VERSION 5.8 ;
BUSBITCHARS "[]" ;
DIVIDERCHAR "/" ;
UNITS
    DATABASE MICRONS 1000 ;
END UNITS

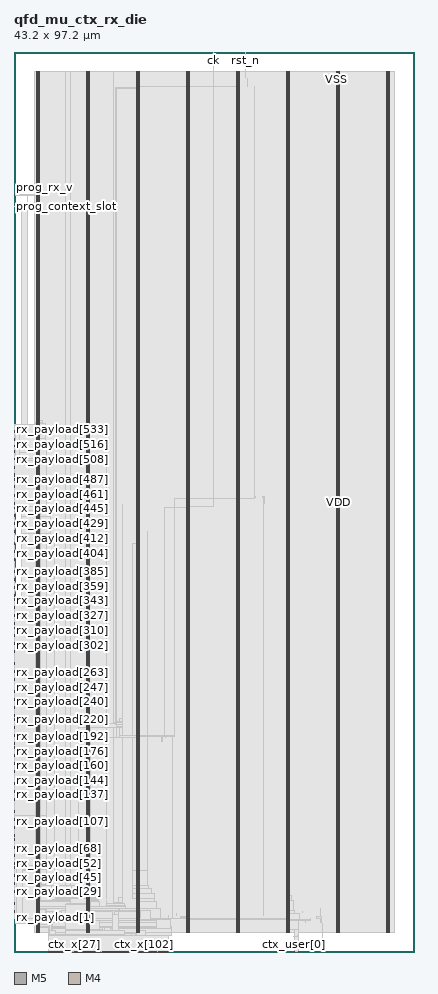
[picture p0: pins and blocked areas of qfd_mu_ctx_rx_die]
MACRO qfd_mu_ctx_rx_die
  FOREIGN qfd_mu_ctx_rx_die 0 0 ;
  CLASS BLOCK ;
  SIZE 43.2 BY 97.2 ;
  PIN ck
    DIRECTION INPUT ;
    USE SIGNAL ;
    PORT
      LAYER M5 ;
        RECT  21.504 97.116 21.528 97.2 ;
    END
  END ck
  PIN ctx_user[0]
    DIRECTION OUTPUT ;
    USE SIGNAL ;
    PORT
      LAYER M5 ;
        RECT  30.24 0 30.264 0.084 ;
    END
  END ctx_user[0]
  PIN ctx_user[1]
    DIRECTION OUTPUT ;
    USE SIGNAL ;
    PORT
      LAYER M5 ;
        RECT  30.72 0 30.744 0.084 ;
    END
  END ctx_user[1]
  PIN ctx_x[0]
    DIRECTION OUTPUT ;
    USE SIGNAL ;
    PORT
      LAYER M5 ;
        RECT  3.744 0 3.768 0.084 ;
    END
  END ctx_x[0]
  PIN ctx_x[100]
    DIRECTION OUTPUT ;
    USE SIGNAL ;
    PORT
      LAYER M5 ;
        RECT  13.824 0 13.848 0.084 ;
    END
  END ctx_x[100]
  PIN ctx_x[101]
    DIRECTION OUTPUT ;
    USE SIGNAL ;
    PORT
      LAYER M5 ;
        RECT  13.92 0 13.944 0.084 ;
    END
  END ctx_x[101]
  PIN ctx_x[102]
    DIRECTION OUTPUT ;
    USE SIGNAL ;
    PORT
      LAYER M5 ;
        RECT  14.016 0 14.04 0.084 ;
    END
  END ctx_x[102]
  PIN ctx_x[103]
    DIRECTION OUTPUT ;
    USE SIGNAL ;
    PORT
      LAYER M5 ;
        RECT  14.112 0 14.136 0.084 ;
    END
  END ctx_x[103]
  PIN ctx_x[104]
    DIRECTION OUTPUT ;
    USE SIGNAL ;
    PORT
      LAYER M5 ;
        RECT  14.208 0 14.232 0.084 ;
    END
  END ctx_x[104]
  PIN ctx_x[105]
    DIRECTION OUTPUT ;
    USE SIGNAL ;
    PORT
      LAYER M5 ;
        RECT  14.304 0 14.328 0.084 ;
    END
  END ctx_x[105]
  PIN ctx_x[106]
    DIRECTION OUTPUT ;
    USE SIGNAL ;
    PORT
      LAYER M5 ;
        RECT  14.4 0 14.424 0.084 ;
    END
  END ctx_x[106]
  PIN ctx_x[107]
    DIRECTION OUTPUT ;
    USE SIGNAL ;
    PORT
      LAYER M5 ;
        RECT  14.544 0 14.568 0.084 ;
    END
  END ctx_x[107]
  PIN ctx_x[108]
    DIRECTION OUTPUT ;
    USE SIGNAL ;
    PORT
      LAYER M5 ;
        RECT  14.64 0 14.664 0.084 ;
    END
  END ctx_x[108]
  PIN ctx_x[109]
    DIRECTION OUTPUT ;
    USE SIGNAL ;
    PORT
      LAYER M5 ;
        RECT  14.736 0 14.76 0.084 ;
    END
  END ctx_x[109]
  PIN ctx_x[10]
    DIRECTION OUTPUT ;
    USE SIGNAL ;
    PORT
      LAYER M5 ;
        RECT  4.752 0 4.776 0.084 ;
    END
  END ctx_x[10]
  PIN ctx_x[110]
    DIRECTION OUTPUT ;
    USE SIGNAL ;
    PORT
      LAYER M5 ;
        RECT  14.832 0 14.856 0.084 ;
    END
  END ctx_x[110]
  PIN ctx_x[111]
    DIRECTION OUTPUT ;
    USE SIGNAL ;
    PORT
      LAYER M5 ;
        RECT  14.928 0 14.952 0.084 ;
    END
  END ctx_x[111]
  PIN ctx_x[112]
    DIRECTION OUTPUT ;
    USE SIGNAL ;
    PORT
      LAYER M5 ;
        RECT  15.024 0 15.048 0.084 ;
    END
  END ctx_x[112]
  PIN ctx_x[113]
    DIRECTION OUTPUT ;
    USE SIGNAL ;
    PORT
      LAYER M5 ;
        RECT  15.12 0 15.144 0.084 ;
    END
  END ctx_x[113]
  PIN ctx_x[114]
    DIRECTION OUTPUT ;
    USE SIGNAL ;
    PORT
      LAYER M5 ;
        RECT  15.216 0 15.24 0.084 ;
    END
  END ctx_x[114]
  PIN ctx_x[115]
    DIRECTION OUTPUT ;
    USE SIGNAL ;
    PORT
      LAYER M5 ;
        RECT  15.312 0 15.336 0.084 ;
    END
  END ctx_x[115]
  PIN ctx_x[116]
    DIRECTION OUTPUT ;
    USE SIGNAL ;
    PORT
      LAYER M5 ;
        RECT  15.408 0 15.432 0.084 ;
    END
  END ctx_x[116]
  PIN ctx_x[117]
    DIRECTION OUTPUT ;
    USE SIGNAL ;
    PORT
      LAYER M5 ;
        RECT  15.552 0 15.576 0.084 ;
    END
  END ctx_x[117]
  PIN ctx_x[118]
    DIRECTION OUTPUT ;
    USE SIGNAL ;
    PORT
      LAYER M5 ;
        RECT  15.648 0 15.672 0.084 ;
    END
  END ctx_x[118]
  PIN ctx_x[119]
    DIRECTION OUTPUT ;
    USE SIGNAL ;
    PORT
      LAYER M5 ;
        RECT  15.744 0 15.768 0.084 ;
    END
  END ctx_x[119]
  PIN ctx_x[11]
    DIRECTION OUTPUT ;
    USE SIGNAL ;
    PORT
      LAYER M5 ;
        RECT  4.848 0 4.872 0.084 ;
    END
  END ctx_x[11]
  PIN ctx_x[120]
    DIRECTION OUTPUT ;
    USE SIGNAL ;
    PORT
      LAYER M5 ;
        RECT  15.84 0 15.864 0.084 ;
    END
  END ctx_x[120]
  PIN ctx_x[121]
    DIRECTION OUTPUT ;
    USE SIGNAL ;
    PORT
      LAYER M5 ;
        RECT  15.936 0 15.96 0.084 ;
    END
  END ctx_x[121]
  PIN ctx_x[122]
    DIRECTION OUTPUT ;
    USE SIGNAL ;
    PORT
      LAYER M5 ;
        RECT  16.032 0 16.056 0.084 ;
    END
  END ctx_x[122]
  PIN ctx_x[123]
    DIRECTION OUTPUT ;
    USE SIGNAL ;
    PORT
      LAYER M5 ;
        RECT  16.128 0 16.152 0.084 ;
    END
  END ctx_x[123]
  PIN ctx_x[124]
    DIRECTION OUTPUT ;
    USE SIGNAL ;
    PORT
      LAYER M5 ;
        RECT  16.224 0 16.248 0.084 ;
    END
  END ctx_x[124]
  PIN ctx_x[125]
    DIRECTION OUTPUT ;
    USE SIGNAL ;
    PORT
      LAYER M5 ;
        RECT  16.32 0 16.344 0.084 ;
    END
  END ctx_x[125]
  PIN ctx_x[126]
    DIRECTION OUTPUT ;
    USE SIGNAL ;
    PORT
      LAYER M5 ;
        RECT  16.416 0 16.44 0.084 ;
    END
  END ctx_x[126]
  PIN ctx_x[127]
    DIRECTION OUTPUT ;
    USE SIGNAL ;
    PORT
      LAYER M5 ;
        RECT  16.56 0 16.584 0.084 ;
    END
  END ctx_x[127]
  PIN ctx_x[128]
    DIRECTION OUTPUT ;
    USE SIGNAL ;
    PORT
      LAYER M5 ;
        RECT  16.656 0 16.68 0.084 ;
    END
  END ctx_x[128]
  PIN ctx_x[12]
    DIRECTION OUTPUT ;
    USE SIGNAL ;
    PORT
      LAYER M5 ;
        RECT  4.944 0 4.968 0.084 ;
    END
  END ctx_x[12]
  PIN ctx_x[13]
    DIRECTION OUTPUT ;
    USE SIGNAL ;
    PORT
      LAYER M5 ;
        RECT  5.04 0 5.064 0.084 ;
    END
  END ctx_x[13]
  PIN ctx_x[14]
    DIRECTION OUTPUT ;
    USE SIGNAL ;
    PORT
      LAYER M5 ;
        RECT  5.136 0 5.16 0.084 ;
    END
  END ctx_x[14]
  PIN ctx_x[15]
    DIRECTION OUTPUT ;
    USE SIGNAL ;
    PORT
      LAYER M5 ;
        RECT  5.232 0 5.256 0.084 ;
    END
  END ctx_x[15]
  PIN ctx_x[16]
    DIRECTION OUTPUT ;
    USE SIGNAL ;
    PORT
      LAYER M5 ;
        RECT  5.328 0 5.352 0.084 ;
    END
  END ctx_x[16]
  PIN ctx_x[17]
    DIRECTION OUTPUT ;
    USE SIGNAL ;
    PORT
      LAYER M5 ;
        RECT  5.472 0 5.496 0.084 ;
    END
  END ctx_x[17]
  PIN ctx_x[18]
    DIRECTION OUTPUT ;
    USE SIGNAL ;
    PORT
      LAYER M5 ;
        RECT  5.568 0 5.592 0.084 ;
    END
  END ctx_x[18]
  PIN ctx_x[19]
    DIRECTION OUTPUT ;
    USE SIGNAL ;
    PORT
      LAYER M5 ;
        RECT  5.664 0 5.688 0.084 ;
    END
  END ctx_x[19]
  PIN ctx_x[1]
    DIRECTION OUTPUT ;
    USE SIGNAL ;
    PORT
      LAYER M5 ;
        RECT  3.84 0 3.864 0.084 ;
    END
  END ctx_x[1]
  PIN ctx_x[20]
    DIRECTION OUTPUT ;
    USE SIGNAL ;
    PORT
      LAYER M5 ;
        RECT  5.76 0 5.784 0.084 ;
    END
  END ctx_x[20]
  PIN ctx_x[21]
    DIRECTION OUTPUT ;
    USE SIGNAL ;
    PORT
      LAYER M5 ;
        RECT  5.856 0 5.88 0.084 ;
    END
  END ctx_x[21]
  PIN ctx_x[22]
    DIRECTION OUTPUT ;
    USE SIGNAL ;
    PORT
      LAYER M5 ;
        RECT  5.952 0 5.976 0.084 ;
    END
  END ctx_x[22]
  PIN ctx_x[23]
    DIRECTION OUTPUT ;
    USE SIGNAL ;
    PORT
      LAYER M5 ;
        RECT  6.048 0 6.072 0.084 ;
    END
  END ctx_x[23]
  PIN ctx_x[24]
    DIRECTION OUTPUT ;
    USE SIGNAL ;
    PORT
      LAYER M5 ;
        RECT  6.144 0 6.168 0.084 ;
    END
  END ctx_x[24]
  PIN ctx_x[25]
    DIRECTION OUTPUT ;
    USE SIGNAL ;
    PORT
      LAYER M5 ;
        RECT  6.24 0 6.264 0.084 ;
    END
  END ctx_x[25]
  PIN ctx_x[26]
    DIRECTION OUTPUT ;
    USE SIGNAL ;
    PORT
      LAYER M5 ;
        RECT  6.336 0 6.36 0.084 ;
    END
  END ctx_x[26]
  PIN ctx_x[27]
    DIRECTION OUTPUT ;
    USE SIGNAL ;
    PORT
      LAYER M5 ;
        RECT  6.48 0 6.504 0.084 ;
    END
  END ctx_x[27]
  PIN ctx_x[28]
    DIRECTION OUTPUT ;
    USE SIGNAL ;
    PORT
      LAYER M5 ;
        RECT  6.576 0 6.6 0.084 ;
    END
  END ctx_x[28]
  PIN ctx_x[29]
    DIRECTION OUTPUT ;
    USE SIGNAL ;
    PORT
      LAYER M5 ;
        RECT  6.672 0 6.696 0.084 ;
    END
  END ctx_x[29]
  PIN ctx_x[2]
    DIRECTION OUTPUT ;
    USE SIGNAL ;
    PORT
      LAYER M5 ;
        RECT  3.936 0 3.96 0.084 ;
    END
  END ctx_x[2]
  PIN ctx_x[30]
    DIRECTION OUTPUT ;
    USE SIGNAL ;
    PORT
      LAYER M5 ;
        RECT  6.768 0 6.792 0.084 ;
    END
  END ctx_x[30]
  PIN ctx_x[31]
    DIRECTION OUTPUT ;
    USE SIGNAL ;
    PORT
      LAYER M5 ;
        RECT  6.864 0 6.888 0.084 ;
    END
  END ctx_x[31]
  PIN ctx_x[32]
    DIRECTION OUTPUT ;
    USE SIGNAL ;
    PORT
      LAYER M5 ;
        RECT  6.96 0 6.984 0.084 ;
    END
  END ctx_x[32]
  PIN ctx_x[33]
    DIRECTION OUTPUT ;
    USE SIGNAL ;
    PORT
      LAYER M5 ;
        RECT  7.056 0 7.08 0.084 ;
    END
  END ctx_x[33]
  PIN ctx_x[34]
    DIRECTION OUTPUT ;
    USE SIGNAL ;
    PORT
      LAYER M5 ;
        RECT  7.152 0 7.176 0.084 ;
    END
  END ctx_x[34]
  PIN ctx_x[35]
    DIRECTION OUTPUT ;
    USE SIGNAL ;
    PORT
      LAYER M5 ;
        RECT  7.248 0 7.272 0.084 ;
    END
  END ctx_x[35]
  PIN ctx_x[36]
    DIRECTION OUTPUT ;
    USE SIGNAL ;
    PORT
      LAYER M5 ;
        RECT  7.344 0 7.368 0.084 ;
    END
  END ctx_x[36]
  PIN ctx_x[37]
    DIRECTION OUTPUT ;
    USE SIGNAL ;
    PORT
      LAYER M5 ;
        RECT  7.488 0 7.512 0.084 ;
    END
  END ctx_x[37]
  PIN ctx_x[38]
    DIRECTION OUTPUT ;
    USE SIGNAL ;
    PORT
      LAYER M5 ;
        RECT  7.584 0 7.608 0.084 ;
    END
  END ctx_x[38]
  PIN ctx_x[39]
    DIRECTION OUTPUT ;
    USE SIGNAL ;
    PORT
      LAYER M5 ;
        RECT  7.68 0 7.704 0.084 ;
    END
  END ctx_x[39]
  PIN ctx_x[3]
    DIRECTION OUTPUT ;
    USE SIGNAL ;
    PORT
      LAYER M5 ;
        RECT  4.032 0 4.056 0.084 ;
    END
  END ctx_x[3]
  PIN ctx_x[40]
    DIRECTION OUTPUT ;
    USE SIGNAL ;
    PORT
      LAYER M5 ;
        RECT  7.776 0 7.8 0.084 ;
    END
  END ctx_x[40]
  PIN ctx_x[41]
    DIRECTION OUTPUT ;
    USE SIGNAL ;
    PORT
      LAYER M5 ;
        RECT  7.872 0 7.896 0.084 ;
    END
  END ctx_x[41]
  PIN ctx_x[42]
    DIRECTION OUTPUT ;
    USE SIGNAL ;
    PORT
      LAYER M5 ;
        RECT  7.968 0 7.992 0.084 ;
    END
  END ctx_x[42]
  PIN ctx_x[43]
    DIRECTION OUTPUT ;
    USE SIGNAL ;
    PORT
      LAYER M5 ;
        RECT  8.064 0 8.088 0.084 ;
    END
  END ctx_x[43]
  PIN ctx_x[44]
    DIRECTION OUTPUT ;
    USE SIGNAL ;
    PORT
      LAYER M5 ;
        RECT  8.16 0 8.184 0.084 ;
    END
  END ctx_x[44]
  PIN ctx_x[45]
    DIRECTION OUTPUT ;
    USE SIGNAL ;
    PORT
      LAYER M5 ;
        RECT  8.256 0 8.28 0.084 ;
    END
  END ctx_x[45]
  PIN ctx_x[46]
    DIRECTION OUTPUT ;
    USE SIGNAL ;
    PORT
      LAYER M5 ;
        RECT  8.352 0 8.376 0.084 ;
    END
  END ctx_x[46]
  PIN ctx_x[47]
    DIRECTION OUTPUT ;
    USE SIGNAL ;
    PORT
      LAYER M5 ;
        RECT  8.496 0 8.52 0.084 ;
    END
  END ctx_x[47]
  PIN ctx_x[48]
    DIRECTION OUTPUT ;
    USE SIGNAL ;
    PORT
      LAYER M5 ;
        RECT  8.592 0 8.616 0.084 ;
    END
  END ctx_x[48]
  PIN ctx_x[49]
    DIRECTION OUTPUT ;
    USE SIGNAL ;
    PORT
      LAYER M5 ;
        RECT  8.688 0 8.712 0.084 ;
    END
  END ctx_x[49]
  PIN ctx_x[4]
    DIRECTION OUTPUT ;
    USE SIGNAL ;
    PORT
      LAYER M5 ;
        RECT  4.128 0 4.152 0.084 ;
    END
  END ctx_x[4]
  PIN ctx_x[50]
    DIRECTION OUTPUT ;
    USE SIGNAL ;
    PORT
      LAYER M5 ;
        RECT  8.784 0 8.808 0.084 ;
    END
  END ctx_x[50]
  PIN ctx_x[51]
    DIRECTION OUTPUT ;
    USE SIGNAL ;
    PORT
      LAYER M5 ;
        RECT  8.88 0 8.904 0.084 ;
    END
  END ctx_x[51]
  PIN ctx_x[52]
    DIRECTION OUTPUT ;
    USE SIGNAL ;
    PORT
      LAYER M5 ;
        RECT  8.976 0 9 0.084 ;
    END
  END ctx_x[52]
  PIN ctx_x[53]
    DIRECTION OUTPUT ;
    USE SIGNAL ;
    PORT
      LAYER M5 ;
        RECT  9.072 0 9.096 0.084 ;
    END
  END ctx_x[53]
  PIN ctx_x[54]
    DIRECTION OUTPUT ;
    USE SIGNAL ;
    PORT
      LAYER M5 ;
        RECT  9.168 0 9.192 0.084 ;
    END
  END ctx_x[54]
  PIN ctx_x[55]
    DIRECTION OUTPUT ;
    USE SIGNAL ;
    PORT
      LAYER M5 ;
        RECT  9.264 0 9.288 0.084 ;
    END
  END ctx_x[55]
  PIN ctx_x[56]
    DIRECTION OUTPUT ;
    USE SIGNAL ;
    PORT
      LAYER M5 ;
        RECT  9.36 0 9.384 0.084 ;
    END
  END ctx_x[56]
  PIN ctx_x[57]
    DIRECTION OUTPUT ;
    USE SIGNAL ;
    PORT
      LAYER M5 ;
        RECT  9.504 0 9.528 0.084 ;
    END
  END ctx_x[57]
  PIN ctx_x[58]
    DIRECTION OUTPUT ;
    USE SIGNAL ;
    PORT
      LAYER M5 ;
        RECT  9.6 0 9.624 0.084 ;
    END
  END ctx_x[58]
  PIN ctx_x[59]
    DIRECTION OUTPUT ;
    USE SIGNAL ;
    PORT
      LAYER M5 ;
        RECT  9.696 0 9.72 0.084 ;
    END
  END ctx_x[59]
  PIN ctx_x[5]
    DIRECTION OUTPUT ;
    USE SIGNAL ;
    PORT
      LAYER M5 ;
        RECT  4.224 0 4.248 0.084 ;
    END
  END ctx_x[5]
  PIN ctx_x[60]
    DIRECTION OUTPUT ;
    USE SIGNAL ;
    PORT
      LAYER M5 ;
        RECT  9.792 0 9.816 0.084 ;
    END
  END ctx_x[60]
  PIN ctx_x[61]
    DIRECTION OUTPUT ;
    USE SIGNAL ;
    PORT
      LAYER M5 ;
        RECT  9.888 0 9.912 0.084 ;
    END
  END ctx_x[61]
  PIN ctx_x[62]
    DIRECTION OUTPUT ;
    USE SIGNAL ;
    PORT
      LAYER M5 ;
        RECT  9.984 0 10.008 0.084 ;
    END
  END ctx_x[62]
  PIN ctx_x[63]
    DIRECTION OUTPUT ;
    USE SIGNAL ;
    PORT
      LAYER M5 ;
        RECT  10.08 0 10.104 0.084 ;
    END
  END ctx_x[63]
  PIN ctx_x[64]
    DIRECTION OUTPUT ;
    USE SIGNAL ;
    PORT
      LAYER M5 ;
        RECT  10.176 0 10.2 0.084 ;
    END
  END ctx_x[64]
  PIN ctx_x[65]
    DIRECTION OUTPUT ;
    USE SIGNAL ;
    PORT
      LAYER M5 ;
        RECT  10.272 0 10.296 0.084 ;
    END
  END ctx_x[65]
  PIN ctx_x[66]
    DIRECTION OUTPUT ;
    USE SIGNAL ;
    PORT
      LAYER M5 ;
        RECT  10.368 0 10.392 0.084 ;
    END
  END ctx_x[66]
  PIN ctx_x[67]
    DIRECTION OUTPUT ;
    USE SIGNAL ;
    PORT
      LAYER M5 ;
        RECT  10.512 0 10.536 0.084 ;
    END
  END ctx_x[67]
  PIN ctx_x[68]
    DIRECTION OUTPUT ;
    USE SIGNAL ;
    PORT
      LAYER M5 ;
        RECT  10.608 0 10.632 0.084 ;
    END
  END ctx_x[68]
  PIN ctx_x[69]
    DIRECTION OUTPUT ;
    USE SIGNAL ;
    PORT
      LAYER M5 ;
        RECT  10.704 0 10.728 0.084 ;
    END
  END ctx_x[69]
  PIN ctx_x[6]
    DIRECTION OUTPUT ;
    USE SIGNAL ;
    PORT
      LAYER M5 ;
        RECT  4.32 0 4.344 0.084 ;
    END
  END ctx_x[6]
  PIN ctx_x[70]
    DIRECTION OUTPUT ;
    USE SIGNAL ;
    PORT
      LAYER M5 ;
        RECT  10.8 0 10.824 0.084 ;
    END
  END ctx_x[70]
  PIN ctx_x[71]
    DIRECTION OUTPUT ;
    USE SIGNAL ;
    PORT
      LAYER M5 ;
        RECT  10.896 0 10.92 0.084 ;
    END
  END ctx_x[71]
  PIN ctx_x[72]
    DIRECTION OUTPUT ;
    USE SIGNAL ;
    PORT
      LAYER M5 ;
        RECT  10.992 0 11.016 0.084 ;
    END
  END ctx_x[72]
  PIN ctx_x[73]
    DIRECTION OUTPUT ;
    USE SIGNAL ;
    PORT
      LAYER M5 ;
        RECT  11.088 0 11.112 0.084 ;
    END
  END ctx_x[73]
  PIN ctx_x[74]
    DIRECTION OUTPUT ;
    USE SIGNAL ;
    PORT
      LAYER M5 ;
        RECT  11.184 0 11.208 0.084 ;
    END
  END ctx_x[74]
  PIN ctx_x[75]
    DIRECTION OUTPUT ;
    USE SIGNAL ;
    PORT
      LAYER M5 ;
        RECT  11.28 0 11.304 0.084 ;
    END
  END ctx_x[75]
  PIN ctx_x[76]
    DIRECTION OUTPUT ;
    USE SIGNAL ;
    PORT
      LAYER M5 ;
        RECT  11.376 0 11.4 0.084 ;
    END
  END ctx_x[76]
  PIN ctx_x[77]
    DIRECTION OUTPUT ;
    USE SIGNAL ;
    PORT
      LAYER M5 ;
        RECT  11.52 0 11.544 0.084 ;
    END
  END ctx_x[77]
  PIN ctx_x[78]
    DIRECTION OUTPUT ;
    USE SIGNAL ;
    PORT
      LAYER M5 ;
        RECT  11.616 0 11.64 0.084 ;
    END
  END ctx_x[78]
  PIN ctx_x[79]
    DIRECTION OUTPUT ;
    USE SIGNAL ;
    PORT
      LAYER M5 ;
        RECT  11.712 0 11.736 0.084 ;
    END
  END ctx_x[79]
  PIN ctx_x[7]
    DIRECTION OUTPUT ;
    USE SIGNAL ;
    PORT
      LAYER M5 ;
        RECT  4.464 0 4.488 0.084 ;
    END
  END ctx_x[7]
  PIN ctx_x[80]
    DIRECTION OUTPUT ;
    USE SIGNAL ;
    PORT
      LAYER M5 ;
        RECT  11.808 0 11.832 0.084 ;
    END
  END ctx_x[80]
  PIN ctx_x[81]
    DIRECTION OUTPUT ;
    USE SIGNAL ;
    PORT
      LAYER M5 ;
        RECT  11.904 0 11.928 0.084 ;
    END
  END ctx_x[81]
  PIN ctx_x[82]
    DIRECTION OUTPUT ;
    USE SIGNAL ;
    PORT
      LAYER M5 ;
        RECT  12 0 12.024 0.084 ;
    END
  END ctx_x[82]
  PIN ctx_x[83]
    DIRECTION OUTPUT ;
    USE SIGNAL ;
    PORT
      LAYER M5 ;
        RECT  12.096 0 12.12 0.084 ;
    END
  END ctx_x[83]
  PIN ctx_x[84]
    DIRECTION OUTPUT ;
    USE SIGNAL ;
    PORT
      LAYER M5 ;
        RECT  12.192 0 12.216 0.084 ;
    END
  END ctx_x[84]
  PIN ctx_x[85]
    DIRECTION OUTPUT ;
    USE SIGNAL ;
    PORT
      LAYER M5 ;
        RECT  12.288 0 12.312 0.084 ;
    END
  END ctx_x[85]
  PIN ctx_x[86]
    DIRECTION OUTPUT ;
    USE SIGNAL ;
    PORT
      LAYER M5 ;
        RECT  12.384 0 12.408 0.084 ;
    END
  END ctx_x[86]
  PIN ctx_x[87]
    DIRECTION OUTPUT ;
    USE SIGNAL ;
    PORT
      LAYER M5 ;
        RECT  12.528 0 12.552 0.084 ;
    END
  END ctx_x[87]
  PIN ctx_x[88]
    DIRECTION OUTPUT ;
    USE SIGNAL ;
    PORT
      LAYER M5 ;
        RECT  12.624 0 12.648 0.084 ;
    END
  END ctx_x[88]
  PIN ctx_x[89]
    DIRECTION OUTPUT ;
    USE SIGNAL ;
    PORT
      LAYER M5 ;
        RECT  12.72 0 12.744 0.084 ;
    END
  END ctx_x[89]
  PIN ctx_x[8]
    DIRECTION OUTPUT ;
    USE SIGNAL ;
    PORT
      LAYER M5 ;
        RECT  4.56 0 4.584 0.084 ;
    END
  END ctx_x[8]
  PIN ctx_x[90]
    DIRECTION OUTPUT ;
    USE SIGNAL ;
    PORT
      LAYER M5 ;
        RECT  12.816 0 12.84 0.084 ;
    END
  END ctx_x[90]
  PIN ctx_x[91]
    DIRECTION OUTPUT ;
    USE SIGNAL ;
    PORT
      LAYER M5 ;
        RECT  12.912 0 12.936 0.084 ;
    END
  END ctx_x[91]
  PIN ctx_x[92]
    DIRECTION OUTPUT ;
    USE SIGNAL ;
    PORT
      LAYER M5 ;
        RECT  13.008 0 13.032 0.084 ;
    END
  END ctx_x[92]
  PIN ctx_x[93]
    DIRECTION OUTPUT ;
    USE SIGNAL ;
    PORT
      LAYER M5 ;
        RECT  13.104 0 13.128 0.084 ;
    END
  END ctx_x[93]
  PIN ctx_x[94]
    DIRECTION OUTPUT ;
    USE SIGNAL ;
    PORT
      LAYER M5 ;
        RECT  13.2 0 13.224 0.084 ;
    END
  END ctx_x[94]
  PIN ctx_x[95]
    DIRECTION OUTPUT ;
    USE SIGNAL ;
    PORT
      LAYER M5 ;
        RECT  13.296 0 13.32 0.084 ;
    END
  END ctx_x[95]
  PIN ctx_x[96]
    DIRECTION OUTPUT ;
    USE SIGNAL ;
    PORT
      LAYER M5 ;
        RECT  13.392 0 13.416 0.084 ;
    END
  END ctx_x[96]
  PIN ctx_x[97]
    DIRECTION OUTPUT ;
    USE SIGNAL ;
    PORT
      LAYER M5 ;
        RECT  13.536 0 13.56 0.084 ;
    END
  END ctx_x[97]
  PIN ctx_x[98]
    DIRECTION OUTPUT ;
    USE SIGNAL ;
    PORT
      LAYER M5 ;
        RECT  13.632 0 13.656 0.084 ;
    END
  END ctx_x[98]
  PIN ctx_x[99]
    DIRECTION OUTPUT ;
    USE SIGNAL ;
    PORT
      LAYER M5 ;
        RECT  13.728 0 13.752 0.084 ;
    END
  END ctx_x[99]
  PIN ctx_x[9]
    DIRECTION OUTPUT ;
    USE SIGNAL ;
    PORT
      LAYER M5 ;
        RECT  4.656 0 4.68 0.084 ;
    END
  END ctx_x[9]
  PIN mu_fault
    DIRECTION OUTPUT ;
    USE SIGNAL ;
    PORT
      LAYER M5 ;
        RECT  33.312 0 33.336 0.084 ;
    END
  END mu_fault
  PIN prog_context_slot
    DIRECTION INPUT ;
    USE SIGNAL ;
    PORT
      LAYER M4 ;
        RECT  0 80.544 0.084 80.568 ;
    END
  END prog_context_slot
  PIN prog_rx_v
    DIRECTION INPUT ;
    USE SIGNAL ;
    PORT
      LAYER M4 ;
        RECT  0 81.744 0.084 81.768 ;
    END
  END prog_rx_v
  PIN rst_n
    DIRECTION INPUT ;
    USE SIGNAL ;
    PORT
      LAYER M5 ;
        RECT  25.008 97.116 25.032 97.2 ;
    END
  END rst_n
  PIN rx_payload[0]
    DIRECTION INPUT ;
    USE SIGNAL ;
    PORT
      LAYER M4 ;
        RECT  0 3.648 0.084 3.672 ;
    END
  END rx_payload[0]
  PIN rx_payload[100]
    DIRECTION INPUT ;
    USE SIGNAL ;
    PORT
      LAYER M4 ;
        RECT  0 13.392 0.084 13.416 ;
    END
  END rx_payload[100]
  PIN rx_payload[101]
    DIRECTION INPUT ;
    USE SIGNAL ;
    PORT
      LAYER M4 ;
        RECT  0 13.488 0.084 13.512 ;
    END
  END rx_payload[101]
  PIN rx_payload[102]
    DIRECTION INPUT ;
    USE SIGNAL ;
    PORT
      LAYER M4 ;
        RECT  0 13.584 0.084 13.608 ;
    END
  END rx_payload[102]
  PIN rx_payload[103]
    DIRECTION INPUT ;
    USE SIGNAL ;
    PORT
      LAYER M4 ;
        RECT  0 13.68 0.084 13.704 ;
    END
  END rx_payload[103]
  PIN rx_payload[104]
    DIRECTION INPUT ;
    USE SIGNAL ;
    PORT
      LAYER M4 ;
        RECT  0 13.776 0.084 13.8 ;
    END
  END rx_payload[104]
  PIN rx_payload[105]
    DIRECTION INPUT ;
    USE SIGNAL ;
    PORT
      LAYER M4 ;
        RECT  0 13.872 0.084 13.896 ;
    END
  END rx_payload[105]
  PIN rx_payload[106]
    DIRECTION INPUT ;
    USE SIGNAL ;
    PORT
      LAYER M4 ;
        RECT  0 13.968 0.084 13.992 ;
    END
  END rx_payload[106]
  PIN rx_payload[107]
    DIRECTION INPUT ;
    USE SIGNAL ;
    PORT
      LAYER M4 ;
        RECT  0 14.064 0.084 14.088 ;
    END
  END rx_payload[107]
  PIN rx_payload[108]
    DIRECTION INPUT ;
    USE SIGNAL ;
    PORT
      LAYER M4 ;
        RECT  0 14.16 0.084 14.184 ;
    END
  END rx_payload[108]
  PIN rx_payload[109]
    DIRECTION INPUT ;
    USE SIGNAL ;
    PORT
      LAYER M4 ;
        RECT  0 14.256 0.084 14.28 ;
    END
  END rx_payload[109]
  PIN rx_payload[10]
    DIRECTION INPUT ;
    USE SIGNAL ;
    PORT
      LAYER M4 ;
        RECT  0 4.608 0.084 4.632 ;
    END
  END rx_payload[10]
  PIN rx_payload[110]
    DIRECTION INPUT ;
    USE SIGNAL ;
    PORT
      LAYER M4 ;
        RECT  0 14.352 0.084 14.376 ;
    END
  END rx_payload[110]
  PIN rx_payload[111]
    DIRECTION INPUT ;
    USE SIGNAL ;
    PORT
      LAYER M4 ;
        RECT  0 14.448 0.084 14.472 ;
    END
  END rx_payload[111]
  PIN rx_payload[112]
    DIRECTION INPUT ;
    USE SIGNAL ;
    PORT
      LAYER M4 ;
        RECT  0 14.544 0.084 14.568 ;
    END
  END rx_payload[112]
  PIN rx_payload[113]
    DIRECTION INPUT ;
    USE SIGNAL ;
    PORT
      LAYER M4 ;
        RECT  0 14.64 0.084 14.664 ;
    END
  END rx_payload[113]
  PIN rx_payload[114]
    DIRECTION INPUT ;
    USE SIGNAL ;
    PORT
      LAYER M4 ;
        RECT  0 14.736 0.084 14.76 ;
    END
  END rx_payload[114]
  PIN rx_payload[115]
    DIRECTION INPUT ;
    USE SIGNAL ;
    PORT
      LAYER M4 ;
        RECT  0 14.832 0.084 14.856 ;
    END
  END rx_payload[115]
  PIN rx_payload[116]
    DIRECTION INPUT ;
    USE SIGNAL ;
    PORT
      LAYER M4 ;
        RECT  0 14.928 0.084 14.952 ;
    END
  END rx_payload[116]
  PIN rx_payload[117]
    DIRECTION INPUT ;
    USE SIGNAL ;
    PORT
      LAYER M4 ;
        RECT  0 15.024 0.084 15.048 ;
    END
  END rx_payload[117]
  PIN rx_payload[118]
    DIRECTION INPUT ;
    USE SIGNAL ;
    PORT
      LAYER M4 ;
        RECT  0 15.12 0.084 15.144 ;
    END
  END rx_payload[118]
  PIN rx_payload[119]
    DIRECTION INPUT ;
    USE SIGNAL ;
    PORT
      LAYER M4 ;
        RECT  0 15.216 0.084 15.24 ;
    END
  END rx_payload[119]
  PIN rx_payload[11]
    DIRECTION INPUT ;
    USE SIGNAL ;
    PORT
      LAYER M4 ;
        RECT  0 4.704 0.084 4.728 ;
    END
  END rx_payload[11]
  PIN rx_payload[120]
    DIRECTION INPUT ;
    USE SIGNAL ;
    PORT
      LAYER M4 ;
        RECT  0 15.312 0.084 15.336 ;
    END
  END rx_payload[120]
  PIN rx_payload[121]
    DIRECTION INPUT ;
    USE SIGNAL ;
    PORT
      LAYER M4 ;
        RECT  0 15.408 0.084 15.432 ;
    END
  END rx_payload[121]
  PIN rx_payload[122]
    DIRECTION INPUT ;
    USE SIGNAL ;
    PORT
      LAYER M4 ;
        RECT  0 15.504 0.084 15.528 ;
    END
  END rx_payload[122]
  PIN rx_payload[123]
    DIRECTION INPUT ;
    USE SIGNAL ;
    PORT
      LAYER M4 ;
        RECT  0 15.6 0.084 15.624 ;
    END
  END rx_payload[123]
  PIN rx_payload[124]
    DIRECTION INPUT ;
    USE SIGNAL ;
    PORT
      LAYER M4 ;
        RECT  0 15.744 0.084 15.768 ;
    END
  END rx_payload[124]
  PIN rx_payload[125]
    DIRECTION INPUT ;
    USE SIGNAL ;
    PORT
      LAYER M4 ;
        RECT  0 15.84 0.084 15.864 ;
    END
  END rx_payload[125]
  PIN rx_payload[126]
    DIRECTION INPUT ;
    USE SIGNAL ;
    PORT
      LAYER M4 ;
        RECT  0 15.936 0.084 15.96 ;
    END
  END rx_payload[126]
  PIN rx_payload[127]
    DIRECTION INPUT ;
    USE SIGNAL ;
    PORT
      LAYER M4 ;
        RECT  0 16.032 0.084 16.056 ;
    END
  END rx_payload[127]
  PIN rx_payload[128]
    DIRECTION INPUT ;
    USE SIGNAL ;
    PORT
      LAYER M4 ;
        RECT  0 16.128 0.084 16.152 ;
    END
  END rx_payload[128]
  PIN rx_payload[129]
    DIRECTION INPUT ;
    USE SIGNAL ;
    PORT
      LAYER M4 ;
        RECT  0 16.224 0.084 16.248 ;
    END
  END rx_payload[129]
  PIN rx_payload[12]
    DIRECTION INPUT ;
    USE SIGNAL ;
    PORT
      LAYER M4 ;
        RECT  0 4.8 0.084 4.824 ;
    END
  END rx_payload[12]
  PIN rx_payload[130]
    DIRECTION INPUT ;
    USE SIGNAL ;
    PORT
      LAYER M4 ;
        RECT  0 16.32 0.084 16.344 ;
    END
  END rx_payload[130]
  PIN rx_payload[131]
    DIRECTION INPUT ;
    USE SIGNAL ;
    PORT
      LAYER M4 ;
        RECT  0 16.416 0.084 16.44 ;
    END
  END rx_payload[131]
  PIN rx_payload[132]
    DIRECTION INPUT ;
    USE SIGNAL ;
    PORT
      LAYER M4 ;
        RECT  0 16.512 0.084 16.536 ;
    END
  END rx_payload[132]
  PIN rx_payload[133]
    DIRECTION INPUT ;
    USE SIGNAL ;
    PORT
      LAYER M4 ;
        RECT  0 16.608 0.084 16.632 ;
    END
  END rx_payload[133]
  PIN rx_payload[134]
    DIRECTION INPUT ;
    USE SIGNAL ;
    PORT
      LAYER M4 ;
        RECT  0 16.704 0.084 16.728 ;
    END
  END rx_payload[134]
  PIN rx_payload[135]
    DIRECTION INPUT ;
    USE SIGNAL ;
    PORT
      LAYER M4 ;
        RECT  0 16.8 0.084 16.824 ;
    END
  END rx_payload[135]
  PIN rx_payload[136]
    DIRECTION INPUT ;
    USE SIGNAL ;
    PORT
      LAYER M4 ;
        RECT  0 16.896 0.084 16.92 ;
    END
  END rx_payload[136]
  PIN rx_payload[137]
    DIRECTION INPUT ;
    USE SIGNAL ;
    PORT
      LAYER M4 ;
        RECT  0 16.992 0.084 17.016 ;
    END
  END rx_payload[137]
  PIN rx_payload[138]
    DIRECTION INPUT ;
    USE SIGNAL ;
    PORT
      LAYER M4 ;
        RECT  0 17.088 0.084 17.112 ;
    END
  END rx_payload[138]
  PIN rx_payload[139]
    DIRECTION INPUT ;
    USE SIGNAL ;
    PORT
      LAYER M4 ;
        RECT  0 17.184 0.084 17.208 ;
    END
  END rx_payload[139]
  PIN rx_payload[13]
    DIRECTION INPUT ;
    USE SIGNAL ;
    PORT
      LAYER M4 ;
        RECT  0 4.896 0.084 4.92 ;
    END
  END rx_payload[13]
  PIN rx_payload[140]
    DIRECTION INPUT ;
    USE SIGNAL ;
    PORT
      LAYER M4 ;
        RECT  0 17.28 0.084 17.304 ;
    END
  END rx_payload[140]
  PIN rx_payload[141]
    DIRECTION INPUT ;
    USE SIGNAL ;
    PORT
      LAYER M4 ;
        RECT  0 17.376 0.084 17.4 ;
    END
  END rx_payload[141]
  PIN rx_payload[142]
    DIRECTION INPUT ;
    USE SIGNAL ;
    PORT
      LAYER M4 ;
        RECT  0 17.472 0.084 17.496 ;
    END
  END rx_payload[142]
  PIN rx_payload[143]
    DIRECTION INPUT ;
    USE SIGNAL ;
    PORT
      LAYER M4 ;
        RECT  0 17.568 0.084 17.592 ;
    END
  END rx_payload[143]
  PIN rx_payload[144]
    DIRECTION INPUT ;
    USE SIGNAL ;
    PORT
      LAYER M4 ;
        RECT  0 17.664 0.084 17.688 ;
    END
  END rx_payload[144]
  PIN rx_payload[145]
    DIRECTION INPUT ;
    USE SIGNAL ;
    PORT
      LAYER M4 ;
        RECT  0 17.76 0.084 17.784 ;
    END
  END rx_payload[145]
  PIN rx_payload[146]
    DIRECTION INPUT ;
    USE SIGNAL ;
    PORT
      LAYER M4 ;
        RECT  0 17.856 0.084 17.88 ;
    END
  END rx_payload[146]
  PIN rx_payload[147]
    DIRECTION INPUT ;
    USE SIGNAL ;
    PORT
      LAYER M4 ;
        RECT  0 17.952 0.084 17.976 ;
    END
  END rx_payload[147]
  PIN rx_payload[148]
    DIRECTION INPUT ;
    USE SIGNAL ;
    PORT
      LAYER M4 ;
        RECT  0 18.048 0.084 18.072 ;
    END
  END rx_payload[148]
  PIN rx_payload[149]
    DIRECTION INPUT ;
    USE SIGNAL ;
    PORT
      LAYER M4 ;
        RECT  0 18.144 0.084 18.168 ;
    END
  END rx_payload[149]
  PIN rx_payload[14]
    DIRECTION INPUT ;
    USE SIGNAL ;
    PORT
      LAYER M4 ;
        RECT  0 4.992 0.084 5.016 ;
    END
  END rx_payload[14]
  PIN rx_payload[150]
    DIRECTION INPUT ;
    USE SIGNAL ;
    PORT
      LAYER M4 ;
        RECT  0 18.24 0.084 18.264 ;
    END
  END rx_payload[150]
  PIN rx_payload[151]
    DIRECTION INPUT ;
    USE SIGNAL ;
    PORT
      LAYER M4 ;
        RECT  0 18.336 0.084 18.36 ;
    END
  END rx_payload[151]
  PIN rx_payload[152]
    DIRECTION INPUT ;
    USE SIGNAL ;
    PORT
      LAYER M4 ;
        RECT  0 18.432 0.084 18.456 ;
    END
  END rx_payload[152]
  PIN rx_payload[153]
    DIRECTION INPUT ;
    USE SIGNAL ;
    PORT
      LAYER M4 ;
        RECT  0 18.528 0.084 18.552 ;
    END
  END rx_payload[153]
  PIN rx_payload[154]
    DIRECTION INPUT ;
    USE SIGNAL ;
    PORT
      LAYER M4 ;
        RECT  0 18.624 0.084 18.648 ;
    END
  END rx_payload[154]
  PIN rx_payload[155]
    DIRECTION INPUT ;
    USE SIGNAL ;
    PORT
      LAYER M4 ;
        RECT  0 18.72 0.084 18.744 ;
    END
  END rx_payload[155]
  PIN rx_payload[156]
    DIRECTION INPUT ;
    USE SIGNAL ;
    PORT
      LAYER M4 ;
        RECT  0 18.816 0.084 18.84 ;
    END
  END rx_payload[156]
  PIN rx_payload[157]
    DIRECTION INPUT ;
    USE SIGNAL ;
    PORT
      LAYER M4 ;
        RECT  0 18.96 0.084 18.984 ;
    END
  END rx_payload[157]
  PIN rx_payload[158]
    DIRECTION INPUT ;
    USE SIGNAL ;
    PORT
      LAYER M4 ;
        RECT  0 19.056 0.084 19.08 ;
    END
  END rx_payload[158]
  PIN rx_payload[159]
    DIRECTION INPUT ;
    USE SIGNAL ;
    PORT
      LAYER M4 ;
        RECT  0 19.152 0.084 19.176 ;
    END
  END rx_payload[159]
  PIN rx_payload[15]
    DIRECTION INPUT ;
    USE SIGNAL ;
    PORT
      LAYER M4 ;
        RECT  0 5.088 0.084 5.112 ;
    END
  END rx_payload[15]
  PIN rx_payload[160]
    DIRECTION INPUT ;
    USE SIGNAL ;
    PORT
      LAYER M4 ;
        RECT  0 19.248 0.084 19.272 ;
    END
  END rx_payload[160]
  PIN rx_payload[161]
    DIRECTION INPUT ;
    USE SIGNAL ;
    PORT
      LAYER M4 ;
        RECT  0 19.344 0.084 19.368 ;
    END
  END rx_payload[161]
  PIN rx_payload[162]
    DIRECTION INPUT ;
    USE SIGNAL ;
    PORT
      LAYER M4 ;
        RECT  0 19.44 0.084 19.464 ;
    END
  END rx_payload[162]
  PIN rx_payload[163]
    DIRECTION INPUT ;
    USE SIGNAL ;
    PORT
      LAYER M4 ;
        RECT  0 19.536 0.084 19.56 ;
    END
  END rx_payload[163]
  PIN rx_payload[164]
    DIRECTION INPUT ;
    USE SIGNAL ;
    PORT
      LAYER M4 ;
        RECT  0 19.632 0.084 19.656 ;
    END
  END rx_payload[164]
  PIN rx_payload[165]
    DIRECTION INPUT ;
    USE SIGNAL ;
    PORT
      LAYER M4 ;
        RECT  0 19.728 0.084 19.752 ;
    END
  END rx_payload[165]
  PIN rx_payload[166]
    DIRECTION INPUT ;
    USE SIGNAL ;
    PORT
      LAYER M4 ;
        RECT  0 19.824 0.084 19.848 ;
    END
  END rx_payload[166]
  PIN rx_payload[167]
    DIRECTION INPUT ;
    USE SIGNAL ;
    PORT
      LAYER M4 ;
        RECT  0 19.92 0.084 19.944 ;
    END
  END rx_payload[167]
  PIN rx_payload[168]
    DIRECTION INPUT ;
    USE SIGNAL ;
    PORT
      LAYER M4 ;
        RECT  0 20.016 0.084 20.04 ;
    END
  END rx_payload[168]
  PIN rx_payload[169]
    DIRECTION INPUT ;
    USE SIGNAL ;
    PORT
      LAYER M4 ;
        RECT  0 20.112 0.084 20.136 ;
    END
  END rx_payload[169]
  PIN rx_payload[16]
    DIRECTION INPUT ;
    USE SIGNAL ;
    PORT
      LAYER M4 ;
        RECT  0 5.184 0.084 5.208 ;
    END
  END rx_payload[16]
  PIN rx_payload[170]
    DIRECTION INPUT ;
    USE SIGNAL ;
    PORT
      LAYER M4 ;
        RECT  0 20.208 0.084 20.232 ;
    END
  END rx_payload[170]
  PIN rx_payload[171]
    DIRECTION INPUT ;
    USE SIGNAL ;
    PORT
      LAYER M4 ;
        RECT  0 20.304 0.084 20.328 ;
    END
  END rx_payload[171]
  PIN rx_payload[172]
    DIRECTION INPUT ;
    USE SIGNAL ;
    PORT
      LAYER M4 ;
        RECT  0 20.4 0.084 20.424 ;
    END
  END rx_payload[172]
  PIN rx_payload[173]
    DIRECTION INPUT ;
    USE SIGNAL ;
    PORT
      LAYER M4 ;
        RECT  0 20.496 0.084 20.52 ;
    END
  END rx_payload[173]
  PIN rx_payload[174]
    DIRECTION INPUT ;
    USE SIGNAL ;
    PORT
      LAYER M4 ;
        RECT  0 20.592 0.084 20.616 ;
    END
  END rx_payload[174]
  PIN rx_payload[175]
    DIRECTION INPUT ;
    USE SIGNAL ;
    PORT
      LAYER M4 ;
        RECT  0 20.688 0.084 20.712 ;
    END
  END rx_payload[175]
  PIN rx_payload[176]
    DIRECTION INPUT ;
    USE SIGNAL ;
    PORT
      LAYER M4 ;
        RECT  0 20.784 0.084 20.808 ;
    END
  END rx_payload[176]
  PIN rx_payload[177]
    DIRECTION INPUT ;
    USE SIGNAL ;
    PORT
      LAYER M4 ;
        RECT  0 20.88 0.084 20.904 ;
    END
  END rx_payload[177]
  PIN rx_payload[178]
    DIRECTION INPUT ;
    USE SIGNAL ;
    PORT
      LAYER M4 ;
        RECT  0 20.976 0.084 21 ;
    END
  END rx_payload[178]
  PIN rx_payload[179]
    DIRECTION INPUT ;
    USE SIGNAL ;
    PORT
      LAYER M4 ;
        RECT  0 21.072 0.084 21.096 ;
    END
  END rx_payload[179]
  PIN rx_payload[17]
    DIRECTION INPUT ;
    USE SIGNAL ;
    PORT
      LAYER M4 ;
        RECT  0 5.28 0.084 5.304 ;
    END
  END rx_payload[17]
  PIN rx_payload[180]
    DIRECTION INPUT ;
    USE SIGNAL ;
    PORT
      LAYER M4 ;
        RECT  0 21.168 0.084 21.192 ;
    END
  END rx_payload[180]
  PIN rx_payload[181]
    DIRECTION INPUT ;
    USE SIGNAL ;
    PORT
      LAYER M4 ;
        RECT  0 21.264 0.084 21.288 ;
    END
  END rx_payload[181]
  PIN rx_payload[182]
    DIRECTION INPUT ;
    USE SIGNAL ;
    PORT
      LAYER M4 ;
        RECT  0 21.36 0.084 21.384 ;
    END
  END rx_payload[182]
  PIN rx_payload[183]
    DIRECTION INPUT ;
    USE SIGNAL ;
    PORT
      LAYER M4 ;
        RECT  0 21.456 0.084 21.48 ;
    END
  END rx_payload[183]
  PIN rx_payload[184]
    DIRECTION INPUT ;
    USE SIGNAL ;
    PORT
      LAYER M4 ;
        RECT  0 21.552 0.084 21.576 ;
    END
  END rx_payload[184]
  PIN rx_payload[185]
    DIRECTION INPUT ;
    USE SIGNAL ;
    PORT
      LAYER M4 ;
        RECT  0 21.648 0.084 21.672 ;
    END
  END rx_payload[185]
  PIN rx_payload[186]
    DIRECTION INPUT ;
    USE SIGNAL ;
    PORT
      LAYER M4 ;
        RECT  0 21.744 0.084 21.768 ;
    END
  END rx_payload[186]
  PIN rx_payload[187]
    DIRECTION INPUT ;
    USE SIGNAL ;
    PORT
      LAYER M4 ;
        RECT  0 21.84 0.084 21.864 ;
    END
  END rx_payload[187]
  PIN rx_payload[188]
    DIRECTION INPUT ;
    USE SIGNAL ;
    PORT
      LAYER M4 ;
        RECT  0 21.936 0.084 21.96 ;
    END
  END rx_payload[188]
  PIN rx_payload[189]
    DIRECTION INPUT ;
    USE SIGNAL ;
    PORT
      LAYER M4 ;
        RECT  0 22.032 0.084 22.056 ;
    END
  END rx_payload[189]
  PIN rx_payload[18]
    DIRECTION INPUT ;
    USE SIGNAL ;
    PORT
      LAYER M4 ;
        RECT  0 5.376 0.084 5.4 ;
    END
  END rx_payload[18]
  PIN rx_payload[190]
    DIRECTION INPUT ;
    USE SIGNAL ;
    PORT
      LAYER M4 ;
        RECT  0 22.128 0.084 22.152 ;
    END
  END rx_payload[190]
  PIN rx_payload[191]
    DIRECTION INPUT ;
    USE SIGNAL ;
    PORT
      LAYER M4 ;
        RECT  0 22.272 0.084 22.296 ;
    END
  END rx_payload[191]
  PIN rx_payload[192]
    DIRECTION INPUT ;
    USE SIGNAL ;
    PORT
      LAYER M4 ;
        RECT  0 22.368 0.084 22.392 ;
    END
  END rx_payload[192]
  PIN rx_payload[193]
    DIRECTION INPUT ;
    USE SIGNAL ;
    PORT
      LAYER M4 ;
        RECT  0 22.464 0.084 22.488 ;
    END
  END rx_payload[193]
  PIN rx_payload[194]
    DIRECTION INPUT ;
    USE SIGNAL ;
    PORT
      LAYER M4 ;
        RECT  0 22.56 0.084 22.584 ;
    END
  END rx_payload[194]
  PIN rx_payload[195]
    DIRECTION INPUT ;
    USE SIGNAL ;
    PORT
      LAYER M4 ;
        RECT  0 22.656 0.084 22.68 ;
    END
  END rx_payload[195]
  PIN rx_payload[196]
    DIRECTION INPUT ;
    USE SIGNAL ;
    PORT
      LAYER M4 ;
        RECT  0 22.752 0.084 22.776 ;
    END
  END rx_payload[196]
  PIN rx_payload[197]
    DIRECTION INPUT ;
    USE SIGNAL ;
    PORT
      LAYER M4 ;
        RECT  0 22.848 0.084 22.872 ;
    END
  END rx_payload[197]
  PIN rx_payload[198]
    DIRECTION INPUT ;
    USE SIGNAL ;
    PORT
      LAYER M4 ;
        RECT  0 22.944 0.084 22.968 ;
    END
  END rx_payload[198]
  PIN rx_payload[199]
    DIRECTION INPUT ;
    USE SIGNAL ;
    PORT
      LAYER M4 ;
        RECT  0 23.04 0.084 23.064 ;
    END
  END rx_payload[199]
  PIN rx_payload[19]
    DIRECTION INPUT ;
    USE SIGNAL ;
    PORT
      LAYER M4 ;
        RECT  0 5.472 0.084 5.496 ;
    END
  END rx_payload[19]
  PIN rx_payload[1]
    DIRECTION INPUT ;
    USE SIGNAL ;
    PORT
      LAYER M4 ;
        RECT  0 3.744 0.084 3.768 ;
    END
  END rx_payload[1]
  PIN rx_payload[200]
    DIRECTION INPUT ;
    USE SIGNAL ;
    PORT
      LAYER M4 ;
        RECT  0 23.136 0.084 23.16 ;
    END
  END rx_payload[200]
  PIN rx_payload[201]
    DIRECTION INPUT ;
    USE SIGNAL ;
    PORT
      LAYER M4 ;
        RECT  0 23.232 0.084 23.256 ;
    END
  END rx_payload[201]
  PIN rx_payload[202]
    DIRECTION INPUT ;
    USE SIGNAL ;
    PORT
      LAYER M4 ;
        RECT  0 23.328 0.084 23.352 ;
    END
  END rx_payload[202]
  PIN rx_payload[203]
    DIRECTION INPUT ;
    USE SIGNAL ;
    PORT
      LAYER M4 ;
        RECT  0 23.424 0.084 23.448 ;
    END
  END rx_payload[203]
  PIN rx_payload[204]
    DIRECTION INPUT ;
    USE SIGNAL ;
    PORT
      LAYER M4 ;
        RECT  0 23.52 0.084 23.544 ;
    END
  END rx_payload[204]
  PIN rx_payload[205]
    DIRECTION INPUT ;
    USE SIGNAL ;
    PORT
      LAYER M4 ;
        RECT  0 23.616 0.084 23.64 ;
    END
  END rx_payload[205]
  PIN rx_payload[206]
    DIRECTION INPUT ;
    USE SIGNAL ;
    PORT
      LAYER M4 ;
        RECT  0 23.712 0.084 23.736 ;
    END
  END rx_payload[206]
  PIN rx_payload[207]
    DIRECTION INPUT ;
    USE SIGNAL ;
    PORT
      LAYER M4 ;
        RECT  0 23.808 0.084 23.832 ;
    END
  END rx_payload[207]
  PIN rx_payload[208]
    DIRECTION INPUT ;
    USE SIGNAL ;
    PORT
      LAYER M4 ;
        RECT  0 23.904 0.084 23.928 ;
    END
  END rx_payload[208]
  PIN rx_payload[209]
    DIRECTION INPUT ;
    USE SIGNAL ;
    PORT
      LAYER M4 ;
        RECT  0 24 0.084 24.024 ;
    END
  END rx_payload[209]
  PIN rx_payload[20]
    DIRECTION INPUT ;
    USE SIGNAL ;
    PORT
      LAYER M4 ;
        RECT  0 5.568 0.084 5.592 ;
    END
  END rx_payload[20]
  PIN rx_payload[210]
    DIRECTION INPUT ;
    USE SIGNAL ;
    PORT
      LAYER M4 ;
        RECT  0 24.096 0.084 24.12 ;
    END
  END rx_payload[210]
  PIN rx_payload[211]
    DIRECTION INPUT ;
    USE SIGNAL ;
    PORT
      LAYER M4 ;
        RECT  0 24.192 0.084 24.216 ;
    END
  END rx_payload[211]
  PIN rx_payload[212]
    DIRECTION INPUT ;
    USE SIGNAL ;
    PORT
      LAYER M4 ;
        RECT  0 24.288 0.084 24.312 ;
    END
  END rx_payload[212]
  PIN rx_payload[213]
    DIRECTION INPUT ;
    USE SIGNAL ;
    PORT
      LAYER M4 ;
        RECT  0 24.384 0.084 24.408 ;
    END
  END rx_payload[213]
  PIN rx_payload[214]
    DIRECTION INPUT ;
    USE SIGNAL ;
    PORT
      LAYER M4 ;
        RECT  0 24.48 0.084 24.504 ;
    END
  END rx_payload[214]
  PIN rx_payload[215]
    DIRECTION INPUT ;
    USE SIGNAL ;
    PORT
      LAYER M4 ;
        RECT  0 24.576 0.084 24.6 ;
    END
  END rx_payload[215]
  PIN rx_payload[216]
    DIRECTION INPUT ;
    USE SIGNAL ;
    PORT
      LAYER M4 ;
        RECT  0 24.672 0.084 24.696 ;
    END
  END rx_payload[216]
  PIN rx_payload[217]
    DIRECTION INPUT ;
    USE SIGNAL ;
    PORT
      LAYER M4 ;
        RECT  0 24.768 0.084 24.792 ;
    END
  END rx_payload[217]
  PIN rx_payload[218]
    DIRECTION INPUT ;
    USE SIGNAL ;
    PORT
      LAYER M4 ;
        RECT  0 24.864 0.084 24.888 ;
    END
  END rx_payload[218]
  PIN rx_payload[219]
    DIRECTION INPUT ;
    USE SIGNAL ;
    PORT
      LAYER M4 ;
        RECT  0 24.96 0.084 24.984 ;
    END
  END rx_payload[219]
  PIN rx_payload[21]
    DIRECTION INPUT ;
    USE SIGNAL ;
    PORT
      LAYER M4 ;
        RECT  0 5.664 0.084 5.688 ;
    END
  END rx_payload[21]
  PIN rx_payload[220]
    DIRECTION INPUT ;
    USE SIGNAL ;
    PORT
      LAYER M4 ;
        RECT  0 25.056 0.084 25.08 ;
    END
  END rx_payload[220]
  PIN rx_payload[221]
    DIRECTION INPUT ;
    USE SIGNAL ;
    PORT
      LAYER M4 ;
        RECT  0 25.152 0.084 25.176 ;
    END
  END rx_payload[221]
  PIN rx_payload[222]
    DIRECTION INPUT ;
    USE SIGNAL ;
    PORT
      LAYER M4 ;
        RECT  0 25.248 0.084 25.272 ;
    END
  END rx_payload[222]
  PIN rx_payload[223]
    DIRECTION INPUT ;
    USE SIGNAL ;
    PORT
      LAYER M4 ;
        RECT  0 25.344 0.084 25.368 ;
    END
  END rx_payload[223]
  PIN rx_payload[224]
    DIRECTION INPUT ;
    USE SIGNAL ;
    PORT
      LAYER M4 ;
        RECT  0 25.488 0.084 25.512 ;
    END
  END rx_payload[224]
  PIN rx_payload[225]
    DIRECTION INPUT ;
    USE SIGNAL ;
    PORT
      LAYER M4 ;
        RECT  0 25.584 0.084 25.608 ;
    END
  END rx_payload[225]
  PIN rx_payload[226]
    DIRECTION INPUT ;
    USE SIGNAL ;
    PORT
      LAYER M4 ;
        RECT  0 25.68 0.084 25.704 ;
    END
  END rx_payload[226]
  PIN rx_payload[227]
    DIRECTION INPUT ;
    USE SIGNAL ;
    PORT
      LAYER M4 ;
        RECT  0 25.776 0.084 25.8 ;
    END
  END rx_payload[227]
  PIN rx_payload[228]
    DIRECTION INPUT ;
    USE SIGNAL ;
    PORT
      LAYER M4 ;
        RECT  0 25.872 0.084 25.896 ;
    END
  END rx_payload[228]
  PIN rx_payload[229]
    DIRECTION INPUT ;
    USE SIGNAL ;
    PORT
      LAYER M4 ;
        RECT  0 25.968 0.084 25.992 ;
    END
  END rx_payload[229]
  PIN rx_payload[22]
    DIRECTION INPUT ;
    USE SIGNAL ;
    PORT
      LAYER M4 ;
        RECT  0 5.76 0.084 5.784 ;
    END
  END rx_payload[22]
  PIN rx_payload[230]
    DIRECTION INPUT ;
    USE SIGNAL ;
    PORT
      LAYER M4 ;
        RECT  0 26.064 0.084 26.088 ;
    END
  END rx_payload[230]
  PIN rx_payload[231]
    DIRECTION INPUT ;
    USE SIGNAL ;
    PORT
      LAYER M4 ;
        RECT  0 26.16 0.084 26.184 ;
    END
  END rx_payload[231]
  PIN rx_payload[232]
    DIRECTION INPUT ;
    USE SIGNAL ;
    PORT
      LAYER M4 ;
        RECT  0 26.256 0.084 26.28 ;
    END
  END rx_payload[232]
  PIN rx_payload[233]
    DIRECTION INPUT ;
    USE SIGNAL ;
    PORT
      LAYER M4 ;
        RECT  0 26.352 0.084 26.376 ;
    END
  END rx_payload[233]
  PIN rx_payload[234]
    DIRECTION INPUT ;
    USE SIGNAL ;
    PORT
      LAYER M4 ;
        RECT  0 26.448 0.084 26.472 ;
    END
  END rx_payload[234]
  PIN rx_payload[235]
    DIRECTION INPUT ;
    USE SIGNAL ;
    PORT
      LAYER M4 ;
        RECT  0 26.544 0.084 26.568 ;
    END
  END rx_payload[235]
  PIN rx_payload[236]
    DIRECTION INPUT ;
    USE SIGNAL ;
    PORT
      LAYER M4 ;
        RECT  0 26.64 0.084 26.664 ;
    END
  END rx_payload[236]
  PIN rx_payload[237]
    DIRECTION INPUT ;
    USE SIGNAL ;
    PORT
      LAYER M4 ;
        RECT  0 26.736 0.084 26.76 ;
    END
  END rx_payload[237]
  PIN rx_payload[238]
    DIRECTION INPUT ;
    USE SIGNAL ;
    PORT
      LAYER M4 ;
        RECT  0 26.832 0.084 26.856 ;
    END
  END rx_payload[238]
  PIN rx_payload[239]
    DIRECTION INPUT ;
    USE SIGNAL ;
    PORT
      LAYER M4 ;
        RECT  0 26.928 0.084 26.952 ;
    END
  END rx_payload[239]
  PIN rx_payload[23]
    DIRECTION INPUT ;
    USE SIGNAL ;
    PORT
      LAYER M4 ;
        RECT  0 5.856 0.084 5.88 ;
    END
  END rx_payload[23]
  PIN rx_payload[240]
    DIRECTION INPUT ;
    USE SIGNAL ;
    PORT
      LAYER M4 ;
        RECT  0 27.024 0.084 27.048 ;
    END
  END rx_payload[240]
  PIN rx_payload[241]
    DIRECTION INPUT ;
    USE SIGNAL ;
    PORT
      LAYER M4 ;
        RECT  0 27.12 0.084 27.144 ;
    END
  END rx_payload[241]
  PIN rx_payload[242]
    DIRECTION INPUT ;
    USE SIGNAL ;
    PORT
      LAYER M4 ;
        RECT  0 27.216 0.084 27.24 ;
    END
  END rx_payload[242]
  PIN rx_payload[243]
    DIRECTION INPUT ;
    USE SIGNAL ;
    PORT
      LAYER M4 ;
        RECT  0 27.312 0.084 27.336 ;
    END
  END rx_payload[243]
  PIN rx_payload[244]
    DIRECTION INPUT ;
    USE SIGNAL ;
    PORT
      LAYER M4 ;
        RECT  0 27.408 0.084 27.432 ;
    END
  END rx_payload[244]
  PIN rx_payload[245]
    DIRECTION INPUT ;
    USE SIGNAL ;
    PORT
      LAYER M4 ;
        RECT  0 27.504 0.084 27.528 ;
    END
  END rx_payload[245]
  PIN rx_payload[246]
    DIRECTION INPUT ;
    USE SIGNAL ;
    PORT
      LAYER M4 ;
        RECT  0 27.6 0.084 27.624 ;
    END
  END rx_payload[246]
  PIN rx_payload[247]
    DIRECTION INPUT ;
    USE SIGNAL ;
    PORT
      LAYER M4 ;
        RECT  0 27.696 0.084 27.72 ;
    END
  END rx_payload[247]
  PIN rx_payload[248]
    DIRECTION INPUT ;
    USE SIGNAL ;
    PORT
      LAYER M4 ;
        RECT  0 27.792 0.084 27.816 ;
    END
  END rx_payload[248]
  PIN rx_payload[249]
    DIRECTION INPUT ;
    USE SIGNAL ;
    PORT
      LAYER M4 ;
        RECT  0 27.888 0.084 27.912 ;
    END
  END rx_payload[249]
  PIN rx_payload[24]
    DIRECTION INPUT ;
    USE SIGNAL ;
    PORT
      LAYER M4 ;
        RECT  0 5.952 0.084 5.976 ;
    END
  END rx_payload[24]
  PIN rx_payload[250]
    DIRECTION INPUT ;
    USE SIGNAL ;
    PORT
      LAYER M4 ;
        RECT  0 27.984 0.084 28.008 ;
    END
  END rx_payload[250]
  PIN rx_payload[251]
    DIRECTION INPUT ;
    USE SIGNAL ;
    PORT
      LAYER M4 ;
        RECT  0 28.08 0.084 28.104 ;
    END
  END rx_payload[251]
  PIN rx_payload[252]
    DIRECTION INPUT ;
    USE SIGNAL ;
    PORT
      LAYER M4 ;
        RECT  0 28.176 0.084 28.2 ;
    END
  END rx_payload[252]
  PIN rx_payload[253]
    DIRECTION INPUT ;
    USE SIGNAL ;
    PORT
      LAYER M4 ;
        RECT  0 28.272 0.084 28.296 ;
    END
  END rx_payload[253]
  PIN rx_payload[254]
    DIRECTION INPUT ;
    USE SIGNAL ;
    PORT
      LAYER M4 ;
        RECT  0 28.368 0.084 28.392 ;
    END
  END rx_payload[254]
  PIN rx_payload[255]
    DIRECTION INPUT ;
    USE SIGNAL ;
    PORT
      LAYER M4 ;
        RECT  0 28.464 0.084 28.488 ;
    END
  END rx_payload[255]
  PIN rx_payload[256]
    DIRECTION INPUT ;
    USE SIGNAL ;
    PORT
      LAYER M4 ;
        RECT  0 28.56 0.084 28.584 ;
    END
  END rx_payload[256]
  PIN rx_payload[257]
    DIRECTION INPUT ;
    USE SIGNAL ;
    PORT
      LAYER M4 ;
        RECT  0 28.704 0.084 28.728 ;
    END
  END rx_payload[257]
  PIN rx_payload[258]
    DIRECTION INPUT ;
    USE SIGNAL ;
    PORT
      LAYER M4 ;
        RECT  0 28.8 0.084 28.824 ;
    END
  END rx_payload[258]
  PIN rx_payload[259]
    DIRECTION INPUT ;
    USE SIGNAL ;
    PORT
      LAYER M4 ;
        RECT  0 28.896 0.084 28.92 ;
    END
  END rx_payload[259]
  PIN rx_payload[25]
    DIRECTION INPUT ;
    USE SIGNAL ;
    PORT
      LAYER M4 ;
        RECT  0 6.096 0.084 6.12 ;
    END
  END rx_payload[25]
  PIN rx_payload[260]
    DIRECTION INPUT ;
    USE SIGNAL ;
    PORT
      LAYER M4 ;
        RECT  0 28.992 0.084 29.016 ;
    END
  END rx_payload[260]
  PIN rx_payload[261]
    DIRECTION INPUT ;
    USE SIGNAL ;
    PORT
      LAYER M4 ;
        RECT  0 29.088 0.084 29.112 ;
    END
  END rx_payload[261]
  PIN rx_payload[262]
    DIRECTION INPUT ;
    USE SIGNAL ;
    PORT
      LAYER M4 ;
        RECT  0 29.184 0.084 29.208 ;
    END
  END rx_payload[262]
  PIN rx_payload[263]
    DIRECTION INPUT ;
    USE SIGNAL ;
    PORT
      LAYER M4 ;
        RECT  0 29.28 0.084 29.304 ;
    END
  END rx_payload[263]
  PIN rx_payload[264]
    DIRECTION INPUT ;
    USE SIGNAL ;
    PORT
      LAYER M4 ;
        RECT  0 29.376 0.084 29.4 ;
    END
  END rx_payload[264]
  PIN rx_payload[265]
    DIRECTION INPUT ;
    USE SIGNAL ;
    PORT
      LAYER M4 ;
        RECT  0 29.472 0.084 29.496 ;
    END
  END rx_payload[265]
  PIN rx_payload[266]
    DIRECTION INPUT ;
    USE SIGNAL ;
    PORT
      LAYER M4 ;
        RECT  0 29.568 0.084 29.592 ;
    END
  END rx_payload[266]
  PIN rx_payload[267]
    DIRECTION INPUT ;
    USE SIGNAL ;
    PORT
      LAYER M4 ;
        RECT  0 29.664 0.084 29.688 ;
    END
  END rx_payload[267]
  PIN rx_payload[268]
    DIRECTION INPUT ;
    USE SIGNAL ;
    PORT
      LAYER M4 ;
        RECT  0 29.76 0.084 29.784 ;
    END
  END rx_payload[268]
  PIN rx_payload[269]
    DIRECTION INPUT ;
    USE SIGNAL ;
    PORT
      LAYER M4 ;
        RECT  0 29.856 0.084 29.88 ;
    END
  END rx_payload[269]
  PIN rx_payload[26]
    DIRECTION INPUT ;
    USE SIGNAL ;
    PORT
      LAYER M4 ;
        RECT  0 6.192 0.084 6.216 ;
    END
  END rx_payload[26]
  PIN rx_payload[270]
    DIRECTION INPUT ;
    USE SIGNAL ;
    PORT
      LAYER M4 ;
        RECT  0 29.952 0.084 29.976 ;
    END
  END rx_payload[270]
  PIN rx_payload[271]
    DIRECTION INPUT ;
    USE SIGNAL ;
    PORT
      LAYER M4 ;
        RECT  0 30.048 0.084 30.072 ;
    END
  END rx_payload[271]
  PIN rx_payload[272]
    DIRECTION INPUT ;
    USE SIGNAL ;
    PORT
      LAYER M4 ;
        RECT  0 30.144 0.084 30.168 ;
    END
  END rx_payload[272]
  PIN rx_payload[273]
    DIRECTION INPUT ;
    USE SIGNAL ;
    PORT
      LAYER M4 ;
        RECT  0 30.24 0.084 30.264 ;
    END
  END rx_payload[273]
  PIN rx_payload[274]
    DIRECTION INPUT ;
    USE SIGNAL ;
    PORT
      LAYER M4 ;
        RECT  0 30.336 0.084 30.36 ;
    END
  END rx_payload[274]
  PIN rx_payload[275]
    DIRECTION INPUT ;
    USE SIGNAL ;
    PORT
      LAYER M4 ;
        RECT  0 30.432 0.084 30.456 ;
    END
  END rx_payload[275]
  PIN rx_payload[276]
    DIRECTION INPUT ;
    USE SIGNAL ;
    PORT
      LAYER M4 ;
        RECT  0 30.528 0.084 30.552 ;
    END
  END rx_payload[276]
  PIN rx_payload[277]
    DIRECTION INPUT ;
    USE SIGNAL ;
    PORT
      LAYER M4 ;
        RECT  0 30.624 0.084 30.648 ;
    END
  END rx_payload[277]
  PIN rx_payload[278]
    DIRECTION INPUT ;
    USE SIGNAL ;
    PORT
      LAYER M4 ;
        RECT  0 30.72 0.084 30.744 ;
    END
  END rx_payload[278]
  PIN rx_payload[279]
    DIRECTION INPUT ;
    USE SIGNAL ;
    PORT
      LAYER M4 ;
        RECT  0 30.816 0.084 30.84 ;
    END
  END rx_payload[279]
  PIN rx_payload[27]
    DIRECTION INPUT ;
    USE SIGNAL ;
    PORT
      LAYER M4 ;
        RECT  0 6.288 0.084 6.312 ;
    END
  END rx_payload[27]
  PIN rx_payload[280]
    DIRECTION INPUT ;
    USE SIGNAL ;
    PORT
      LAYER M4 ;
        RECT  0 30.912 0.084 30.936 ;
    END
  END rx_payload[280]
  PIN rx_payload[281]
    DIRECTION INPUT ;
    USE SIGNAL ;
    PORT
      LAYER M4 ;
        RECT  0 31.008 0.084 31.032 ;
    END
  END rx_payload[281]
  PIN rx_payload[282]
    DIRECTION INPUT ;
    USE SIGNAL ;
    PORT
      LAYER M4 ;
        RECT  0 31.104 0.084 31.128 ;
    END
  END rx_payload[282]
  PIN rx_payload[283]
    DIRECTION INPUT ;
    USE SIGNAL ;
    PORT
      LAYER M4 ;
        RECT  0 31.2 0.084 31.224 ;
    END
  END rx_payload[283]
  PIN rx_payload[284]
    DIRECTION INPUT ;
    USE SIGNAL ;
    PORT
      LAYER M4 ;
        RECT  0 31.296 0.084 31.32 ;
    END
  END rx_payload[284]
  PIN rx_payload[285]
    DIRECTION INPUT ;
    USE SIGNAL ;
    PORT
      LAYER M4 ;
        RECT  0 31.392 0.084 31.416 ;
    END
  END rx_payload[285]
  PIN rx_payload[286]
    DIRECTION INPUT ;
    USE SIGNAL ;
    PORT
      LAYER M4 ;
        RECT  0 31.488 0.084 31.512 ;
    END
  END rx_payload[286]
  PIN rx_payload[287]
    DIRECTION INPUT ;
    USE SIGNAL ;
    PORT
      LAYER M4 ;
        RECT  0 31.584 0.084 31.608 ;
    END
  END rx_payload[287]
  PIN rx_payload[288]
    DIRECTION INPUT ;
    USE SIGNAL ;
    PORT
      LAYER M4 ;
        RECT  0 31.68 0.084 31.704 ;
    END
  END rx_payload[288]
  PIN rx_payload[289]
    DIRECTION INPUT ;
    USE SIGNAL ;
    PORT
      LAYER M4 ;
        RECT  0 31.776 0.084 31.8 ;
    END
  END rx_payload[289]
  PIN rx_payload[28]
    DIRECTION INPUT ;
    USE SIGNAL ;
    PORT
      LAYER M4 ;
        RECT  0 6.384 0.084 6.408 ;
    END
  END rx_payload[28]
  PIN rx_payload[290]
    DIRECTION INPUT ;
    USE SIGNAL ;
    PORT
      LAYER M4 ;
        RECT  0 31.92 0.084 31.944 ;
    END
  END rx_payload[290]
  PIN rx_payload[291]
    DIRECTION INPUT ;
    USE SIGNAL ;
    PORT
      LAYER M4 ;
        RECT  0 32.016 0.084 32.04 ;
    END
  END rx_payload[291]
  PIN rx_payload[292]
    DIRECTION INPUT ;
    USE SIGNAL ;
    PORT
      LAYER M4 ;
        RECT  0 32.112 0.084 32.136 ;
    END
  END rx_payload[292]
  PIN rx_payload[293]
    DIRECTION INPUT ;
    USE SIGNAL ;
    PORT
      LAYER M4 ;
        RECT  0 32.208 0.084 32.232 ;
    END
  END rx_payload[293]
  PIN rx_payload[294]
    DIRECTION INPUT ;
    USE SIGNAL ;
    PORT
      LAYER M4 ;
        RECT  0 32.304 0.084 32.328 ;
    END
  END rx_payload[294]
  PIN rx_payload[295]
    DIRECTION INPUT ;
    USE SIGNAL ;
    PORT
      LAYER M4 ;
        RECT  0 32.4 0.084 32.424 ;
    END
  END rx_payload[295]
  PIN rx_payload[296]
    DIRECTION INPUT ;
    USE SIGNAL ;
    PORT
      LAYER M4 ;
        RECT  0 32.496 0.084 32.52 ;
    END
  END rx_payload[296]
  PIN rx_payload[297]
    DIRECTION INPUT ;
    USE SIGNAL ;
    PORT
      LAYER M4 ;
        RECT  0 32.592 0.084 32.616 ;
    END
  END rx_payload[297]
  PIN rx_payload[298]
    DIRECTION INPUT ;
    USE SIGNAL ;
    PORT
      LAYER M4 ;
        RECT  0 32.688 0.084 32.712 ;
    END
  END rx_payload[298]
  PIN rx_payload[299]
    DIRECTION INPUT ;
    USE SIGNAL ;
    PORT
      LAYER M4 ;
        RECT  0 32.784 0.084 32.808 ;
    END
  END rx_payload[299]
  PIN rx_payload[29]
    DIRECTION INPUT ;
    USE SIGNAL ;
    PORT
      LAYER M4 ;
        RECT  0 6.48 0.084 6.504 ;
    END
  END rx_payload[29]
  PIN rx_payload[2]
    DIRECTION INPUT ;
    USE SIGNAL ;
    PORT
      LAYER M4 ;
        RECT  0 3.84 0.084 3.864 ;
    END
  END rx_payload[2]
  PIN rx_payload[300]
    DIRECTION INPUT ;
    USE SIGNAL ;
    PORT
      LAYER M4 ;
        RECT  0 32.88 0.084 32.904 ;
    END
  END rx_payload[300]
  PIN rx_payload[301]
    DIRECTION INPUT ;
    USE SIGNAL ;
    PORT
      LAYER M4 ;
        RECT  0 32.976 0.084 33 ;
    END
  END rx_payload[301]
  PIN rx_payload[302]
    DIRECTION INPUT ;
    USE SIGNAL ;
    PORT
      LAYER M4 ;
        RECT  0 33.072 0.084 33.096 ;
    END
  END rx_payload[302]
  PIN rx_payload[303]
    DIRECTION INPUT ;
    USE SIGNAL ;
    PORT
      LAYER M4 ;
        RECT  0 33.168 0.084 33.192 ;
    END
  END rx_payload[303]
  PIN rx_payload[304]
    DIRECTION INPUT ;
    USE SIGNAL ;
    PORT
      LAYER M4 ;
        RECT  0 33.264 0.084 33.288 ;
    END
  END rx_payload[304]
  PIN rx_payload[305]
    DIRECTION INPUT ;
    USE SIGNAL ;
    PORT
      LAYER M4 ;
        RECT  0 33.36 0.084 33.384 ;
    END
  END rx_payload[305]
  PIN rx_payload[306]
    DIRECTION INPUT ;
    USE SIGNAL ;
    PORT
      LAYER M4 ;
        RECT  0 33.456 0.084 33.48 ;
    END
  END rx_payload[306]
  PIN rx_payload[307]
    DIRECTION INPUT ;
    USE SIGNAL ;
    PORT
      LAYER M4 ;
        RECT  0 33.552 0.084 33.576 ;
    END
  END rx_payload[307]
  PIN rx_payload[308]
    DIRECTION INPUT ;
    USE SIGNAL ;
    PORT
      LAYER M4 ;
        RECT  0 33.648 0.084 33.672 ;
    END
  END rx_payload[308]
  PIN rx_payload[309]
    DIRECTION INPUT ;
    USE SIGNAL ;
    PORT
      LAYER M4 ;
        RECT  0 33.744 0.084 33.768 ;
    END
  END rx_payload[309]
  PIN rx_payload[30]
    DIRECTION INPUT ;
    USE SIGNAL ;
    PORT
      LAYER M4 ;
        RECT  0 6.576 0.084 6.6 ;
    END
  END rx_payload[30]
  PIN rx_payload[310]
    DIRECTION INPUT ;
    USE SIGNAL ;
    PORT
      LAYER M4 ;
        RECT  0 33.84 0.084 33.864 ;
    END
  END rx_payload[310]
  PIN rx_payload[311]
    DIRECTION INPUT ;
    USE SIGNAL ;
    PORT
      LAYER M4 ;
        RECT  0 33.936 0.084 33.96 ;
    END
  END rx_payload[311]
  PIN rx_payload[312]
    DIRECTION INPUT ;
    USE SIGNAL ;
    PORT
      LAYER M4 ;
        RECT  0 34.032 0.084 34.056 ;
    END
  END rx_payload[312]
  PIN rx_payload[313]
    DIRECTION INPUT ;
    USE SIGNAL ;
    PORT
      LAYER M4 ;
        RECT  0 34.128 0.084 34.152 ;
    END
  END rx_payload[313]
  PIN rx_payload[314]
    DIRECTION INPUT ;
    USE SIGNAL ;
    PORT
      LAYER M4 ;
        RECT  0 34.224 0.084 34.248 ;
    END
  END rx_payload[314]
  PIN rx_payload[315]
    DIRECTION INPUT ;
    USE SIGNAL ;
    PORT
      LAYER M4 ;
        RECT  0 34.32 0.084 34.344 ;
    END
  END rx_payload[315]
  PIN rx_payload[316]
    DIRECTION INPUT ;
    USE SIGNAL ;
    PORT
      LAYER M4 ;
        RECT  0 34.416 0.084 34.44 ;
    END
  END rx_payload[316]
  PIN rx_payload[317]
    DIRECTION INPUT ;
    USE SIGNAL ;
    PORT
      LAYER M4 ;
        RECT  0 34.512 0.084 34.536 ;
    END
  END rx_payload[317]
  PIN rx_payload[318]
    DIRECTION INPUT ;
    USE SIGNAL ;
    PORT
      LAYER M4 ;
        RECT  0 34.608 0.084 34.632 ;
    END
  END rx_payload[318]
  PIN rx_payload[319]
    DIRECTION INPUT ;
    USE SIGNAL ;
    PORT
      LAYER M4 ;
        RECT  0 34.704 0.084 34.728 ;
    END
  END rx_payload[319]
  PIN rx_payload[31]
    DIRECTION INPUT ;
    USE SIGNAL ;
    PORT
      LAYER M4 ;
        RECT  0 6.672 0.084 6.696 ;
    END
  END rx_payload[31]
  PIN rx_payload[320]
    DIRECTION INPUT ;
    USE SIGNAL ;
    PORT
      LAYER M4 ;
        RECT  0 34.8 0.084 34.824 ;
    END
  END rx_payload[320]
  PIN rx_payload[321]
    DIRECTION INPUT ;
    USE SIGNAL ;
    PORT
      LAYER M4 ;
        RECT  0 34.896 0.084 34.92 ;
    END
  END rx_payload[321]
  PIN rx_payload[322]
    DIRECTION INPUT ;
    USE SIGNAL ;
    PORT
      LAYER M4 ;
        RECT  0 34.992 0.084 35.016 ;
    END
  END rx_payload[322]
  PIN rx_payload[323]
    DIRECTION INPUT ;
    USE SIGNAL ;
    PORT
      LAYER M4 ;
        RECT  0 35.136 0.084 35.16 ;
    END
  END rx_payload[323]
  PIN rx_payload[324]
    DIRECTION INPUT ;
    USE SIGNAL ;
    PORT
      LAYER M4 ;
        RECT  0 35.232 0.084 35.256 ;
    END
  END rx_payload[324]
  PIN rx_payload[325]
    DIRECTION INPUT ;
    USE SIGNAL ;
    PORT
      LAYER M4 ;
        RECT  0 35.328 0.084 35.352 ;
    END
  END rx_payload[325]
  PIN rx_payload[326]
    DIRECTION INPUT ;
    USE SIGNAL ;
    PORT
      LAYER M4 ;
        RECT  0 35.424 0.084 35.448 ;
    END
  END rx_payload[326]
  PIN rx_payload[327]
    DIRECTION INPUT ;
    USE SIGNAL ;
    PORT
      LAYER M4 ;
        RECT  0 35.52 0.084 35.544 ;
    END
  END rx_payload[327]
  PIN rx_payload[328]
    DIRECTION INPUT ;
    USE SIGNAL ;
    PORT
      LAYER M4 ;
        RECT  0 35.616 0.084 35.64 ;
    END
  END rx_payload[328]
  PIN rx_payload[329]
    DIRECTION INPUT ;
    USE SIGNAL ;
    PORT
      LAYER M4 ;
        RECT  0 35.712 0.084 35.736 ;
    END
  END rx_payload[329]
  PIN rx_payload[32]
    DIRECTION INPUT ;
    USE SIGNAL ;
    PORT
      LAYER M4 ;
        RECT  0 6.768 0.084 6.792 ;
    END
  END rx_payload[32]
  PIN rx_payload[330]
    DIRECTION INPUT ;
    USE SIGNAL ;
    PORT
      LAYER M4 ;
        RECT  0 35.808 0.084 35.832 ;
    END
  END rx_payload[330]
  PIN rx_payload[331]
    DIRECTION INPUT ;
    USE SIGNAL ;
    PORT
      LAYER M4 ;
        RECT  0 35.904 0.084 35.928 ;
    END
  END rx_payload[331]
  PIN rx_payload[332]
    DIRECTION INPUT ;
    USE SIGNAL ;
    PORT
      LAYER M4 ;
        RECT  0 36 0.084 36.024 ;
    END
  END rx_payload[332]
  PIN rx_payload[333]
    DIRECTION INPUT ;
    USE SIGNAL ;
    PORT
      LAYER M4 ;
        RECT  0 36.096 0.084 36.12 ;
    END
  END rx_payload[333]
  PIN rx_payload[334]
    DIRECTION INPUT ;
    USE SIGNAL ;
    PORT
      LAYER M4 ;
        RECT  0 36.192 0.084 36.216 ;
    END
  END rx_payload[334]
  PIN rx_payload[335]
    DIRECTION INPUT ;
    USE SIGNAL ;
    PORT
      LAYER M4 ;
        RECT  0 36.288 0.084 36.312 ;
    END
  END rx_payload[335]
  PIN rx_payload[336]
    DIRECTION INPUT ;
    USE SIGNAL ;
    PORT
      LAYER M4 ;
        RECT  0 36.384 0.084 36.408 ;
    END
  END rx_payload[336]
  PIN rx_payload[337]
    DIRECTION INPUT ;
    USE SIGNAL ;
    PORT
      LAYER M4 ;
        RECT  0 36.48 0.084 36.504 ;
    END
  END rx_payload[337]
  PIN rx_payload[338]
    DIRECTION INPUT ;
    USE SIGNAL ;
    PORT
      LAYER M4 ;
        RECT  0 36.576 0.084 36.6 ;
    END
  END rx_payload[338]
  PIN rx_payload[339]
    DIRECTION INPUT ;
    USE SIGNAL ;
    PORT
      LAYER M4 ;
        RECT  0 36.672 0.084 36.696 ;
    END
  END rx_payload[339]
  PIN rx_payload[33]
    DIRECTION INPUT ;
    USE SIGNAL ;
    PORT
      LAYER M4 ;
        RECT  0 6.864 0.084 6.888 ;
    END
  END rx_payload[33]
  PIN rx_payload[340]
    DIRECTION INPUT ;
    USE SIGNAL ;
    PORT
      LAYER M4 ;
        RECT  0 36.768 0.084 36.792 ;
    END
  END rx_payload[340]
  PIN rx_payload[341]
    DIRECTION INPUT ;
    USE SIGNAL ;
    PORT
      LAYER M4 ;
        RECT  0 36.864 0.084 36.888 ;
    END
  END rx_payload[341]
  PIN rx_payload[342]
    DIRECTION INPUT ;
    USE SIGNAL ;
    PORT
      LAYER M4 ;
        RECT  0 36.96 0.084 36.984 ;
    END
  END rx_payload[342]
  PIN rx_payload[343]
    DIRECTION INPUT ;
    USE SIGNAL ;
    PORT
      LAYER M4 ;
        RECT  0 37.056 0.084 37.08 ;
    END
  END rx_payload[343]
  PIN rx_payload[344]
    DIRECTION INPUT ;
    USE SIGNAL ;
    PORT
      LAYER M4 ;
        RECT  0 37.152 0.084 37.176 ;
    END
  END rx_payload[344]
  PIN rx_payload[345]
    DIRECTION INPUT ;
    USE SIGNAL ;
    PORT
      LAYER M4 ;
        RECT  0 37.248 0.084 37.272 ;
    END
  END rx_payload[345]
  PIN rx_payload[346]
    DIRECTION INPUT ;
    USE SIGNAL ;
    PORT
      LAYER M4 ;
        RECT  0 37.344 0.084 37.368 ;
    END
  END rx_payload[346]
  PIN rx_payload[347]
    DIRECTION INPUT ;
    USE SIGNAL ;
    PORT
      LAYER M4 ;
        RECT  0 37.44 0.084 37.464 ;
    END
  END rx_payload[347]
  PIN rx_payload[348]
    DIRECTION INPUT ;
    USE SIGNAL ;
    PORT
      LAYER M4 ;
        RECT  0 37.536 0.084 37.56 ;
    END
  END rx_payload[348]
  PIN rx_payload[349]
    DIRECTION INPUT ;
    USE SIGNAL ;
    PORT
      LAYER M4 ;
        RECT  0 37.632 0.084 37.656 ;
    END
  END rx_payload[349]
  PIN rx_payload[34]
    DIRECTION INPUT ;
    USE SIGNAL ;
    PORT
      LAYER M4 ;
        RECT  0 6.96 0.084 6.984 ;
    END
  END rx_payload[34]
  PIN rx_payload[350]
    DIRECTION INPUT ;
    USE SIGNAL ;
    PORT
      LAYER M4 ;
        RECT  0 37.728 0.084 37.752 ;
    END
  END rx_payload[350]
  PIN rx_payload[351]
    DIRECTION INPUT ;
    USE SIGNAL ;
    PORT
      LAYER M4 ;
        RECT  0 37.824 0.084 37.848 ;
    END
  END rx_payload[351]
  PIN rx_payload[352]
    DIRECTION INPUT ;
    USE SIGNAL ;
    PORT
      LAYER M4 ;
        RECT  0 37.92 0.084 37.944 ;
    END
  END rx_payload[352]
  PIN rx_payload[353]
    DIRECTION INPUT ;
    USE SIGNAL ;
    PORT
      LAYER M4 ;
        RECT  0 38.016 0.084 38.04 ;
    END
  END rx_payload[353]
  PIN rx_payload[354]
    DIRECTION INPUT ;
    USE SIGNAL ;
    PORT
      LAYER M4 ;
        RECT  0 38.112 0.084 38.136 ;
    END
  END rx_payload[354]
  PIN rx_payload[355]
    DIRECTION INPUT ;
    USE SIGNAL ;
    PORT
      LAYER M4 ;
        RECT  0 38.208 0.084 38.232 ;
    END
  END rx_payload[355]
  PIN rx_payload[356]
    DIRECTION INPUT ;
    USE SIGNAL ;
    PORT
      LAYER M4 ;
        RECT  0 38.304 0.084 38.328 ;
    END
  END rx_payload[356]
  PIN rx_payload[357]
    DIRECTION INPUT ;
    USE SIGNAL ;
    PORT
      LAYER M4 ;
        RECT  0 38.448 0.084 38.472 ;
    END
  END rx_payload[357]
  PIN rx_payload[358]
    DIRECTION INPUT ;
    USE SIGNAL ;
    PORT
      LAYER M4 ;
        RECT  0 38.544 0.084 38.568 ;
    END
  END rx_payload[358]
  PIN rx_payload[359]
    DIRECTION INPUT ;
    USE SIGNAL ;
    PORT
      LAYER M4 ;
        RECT  0 38.64 0.084 38.664 ;
    END
  END rx_payload[359]
  PIN rx_payload[35]
    DIRECTION INPUT ;
    USE SIGNAL ;
    PORT
      LAYER M4 ;
        RECT  0 7.056 0.084 7.08 ;
    END
  END rx_payload[35]
  PIN rx_payload[360]
    DIRECTION INPUT ;
    USE SIGNAL ;
    PORT
      LAYER M4 ;
        RECT  0 38.736 0.084 38.76 ;
    END
  END rx_payload[360]
  PIN rx_payload[361]
    DIRECTION INPUT ;
    USE SIGNAL ;
    PORT
      LAYER M4 ;
        RECT  0 38.832 0.084 38.856 ;
    END
  END rx_payload[361]
  PIN rx_payload[362]
    DIRECTION INPUT ;
    USE SIGNAL ;
    PORT
      LAYER M4 ;
        RECT  0 38.928 0.084 38.952 ;
    END
  END rx_payload[362]
  PIN rx_payload[363]
    DIRECTION INPUT ;
    USE SIGNAL ;
    PORT
      LAYER M4 ;
        RECT  0 39.024 0.084 39.048 ;
    END
  END rx_payload[363]
  PIN rx_payload[364]
    DIRECTION INPUT ;
    USE SIGNAL ;
    PORT
      LAYER M4 ;
        RECT  0 39.12 0.084 39.144 ;
    END
  END rx_payload[364]
  PIN rx_payload[365]
    DIRECTION INPUT ;
    USE SIGNAL ;
    PORT
      LAYER M4 ;
        RECT  0 39.216 0.084 39.24 ;
    END
  END rx_payload[365]
  PIN rx_payload[366]
    DIRECTION INPUT ;
    USE SIGNAL ;
    PORT
      LAYER M4 ;
        RECT  0 39.312 0.084 39.336 ;
    END
  END rx_payload[366]
  PIN rx_payload[367]
    DIRECTION INPUT ;
    USE SIGNAL ;
    PORT
      LAYER M4 ;
        RECT  0 39.408 0.084 39.432 ;
    END
  END rx_payload[367]
  PIN rx_payload[368]
    DIRECTION INPUT ;
    USE SIGNAL ;
    PORT
      LAYER M4 ;
        RECT  0 39.504 0.084 39.528 ;
    END
  END rx_payload[368]
  PIN rx_payload[369]
    DIRECTION INPUT ;
    USE SIGNAL ;
    PORT
      LAYER M4 ;
        RECT  0 39.6 0.084 39.624 ;
    END
  END rx_payload[369]
  PIN rx_payload[36]
    DIRECTION INPUT ;
    USE SIGNAL ;
    PORT
      LAYER M4 ;
        RECT  0 7.152 0.084 7.176 ;
    END
  END rx_payload[36]
  PIN rx_payload[370]
    DIRECTION INPUT ;
    USE SIGNAL ;
    PORT
      LAYER M4 ;
        RECT  0 39.696 0.084 39.72 ;
    END
  END rx_payload[370]
  PIN rx_payload[371]
    DIRECTION INPUT ;
    USE SIGNAL ;
    PORT
      LAYER M4 ;
        RECT  0 39.792 0.084 39.816 ;
    END
  END rx_payload[371]
  PIN rx_payload[372]
    DIRECTION INPUT ;
    USE SIGNAL ;
    PORT
      LAYER M4 ;
        RECT  0 39.888 0.084 39.912 ;
    END
  END rx_payload[372]
  PIN rx_payload[373]
    DIRECTION INPUT ;
    USE SIGNAL ;
    PORT
      LAYER M4 ;
        RECT  0 39.984 0.084 40.008 ;
    END
  END rx_payload[373]
  PIN rx_payload[374]
    DIRECTION INPUT ;
    USE SIGNAL ;
    PORT
      LAYER M4 ;
        RECT  0 40.08 0.084 40.104 ;
    END
  END rx_payload[374]
  PIN rx_payload[375]
    DIRECTION INPUT ;
    USE SIGNAL ;
    PORT
      LAYER M4 ;
        RECT  0 40.176 0.084 40.2 ;
    END
  END rx_payload[375]
  PIN rx_payload[376]
    DIRECTION INPUT ;
    USE SIGNAL ;
    PORT
      LAYER M4 ;
        RECT  0 40.272 0.084 40.296 ;
    END
  END rx_payload[376]
  PIN rx_payload[377]
    DIRECTION INPUT ;
    USE SIGNAL ;
    PORT
      LAYER M4 ;
        RECT  0 40.368 0.084 40.392 ;
    END
  END rx_payload[377]
  PIN rx_payload[378]
    DIRECTION INPUT ;
    USE SIGNAL ;
    PORT
      LAYER M4 ;
        RECT  0 40.464 0.084 40.488 ;
    END
  END rx_payload[378]
  PIN rx_payload[379]
    DIRECTION INPUT ;
    USE SIGNAL ;
    PORT
      LAYER M4 ;
        RECT  0 40.56 0.084 40.584 ;
    END
  END rx_payload[379]
  PIN rx_payload[37]
    DIRECTION INPUT ;
    USE SIGNAL ;
    PORT
      LAYER M4 ;
        RECT  0 7.248 0.084 7.272 ;
    END
  END rx_payload[37]
  PIN rx_payload[380]
    DIRECTION INPUT ;
    USE SIGNAL ;
    PORT
      LAYER M4 ;
        RECT  0 40.656 0.084 40.68 ;
    END
  END rx_payload[380]
  PIN rx_payload[381]
    DIRECTION INPUT ;
    USE SIGNAL ;
    PORT
      LAYER M4 ;
        RECT  0 40.752 0.084 40.776 ;
    END
  END rx_payload[381]
  PIN rx_payload[382]
    DIRECTION INPUT ;
    USE SIGNAL ;
    PORT
      LAYER M4 ;
        RECT  0 40.848 0.084 40.872 ;
    END
  END rx_payload[382]
  PIN rx_payload[383]
    DIRECTION INPUT ;
    USE SIGNAL ;
    PORT
      LAYER M4 ;
        RECT  0 40.944 0.084 40.968 ;
    END
  END rx_payload[383]
  PIN rx_payload[384]
    DIRECTION INPUT ;
    USE SIGNAL ;
    PORT
      LAYER M4 ;
        RECT  0 41.04 0.084 41.064 ;
    END
  END rx_payload[384]
  PIN rx_payload[385]
    DIRECTION INPUT ;
    USE SIGNAL ;
    PORT
      LAYER M4 ;
        RECT  0 41.136 0.084 41.16 ;
    END
  END rx_payload[385]
  PIN rx_payload[386]
    DIRECTION INPUT ;
    USE SIGNAL ;
    PORT
      LAYER M4 ;
        RECT  0 41.232 0.084 41.256 ;
    END
  END rx_payload[386]
  PIN rx_payload[387]
    DIRECTION INPUT ;
    USE SIGNAL ;
    PORT
      LAYER M4 ;
        RECT  0 41.328 0.084 41.352 ;
    END
  END rx_payload[387]
  PIN rx_payload[388]
    DIRECTION INPUT ;
    USE SIGNAL ;
    PORT
      LAYER M4 ;
        RECT  0 41.424 0.084 41.448 ;
    END
  END rx_payload[388]
  PIN rx_payload[389]
    DIRECTION INPUT ;
    USE SIGNAL ;
    PORT
      LAYER M4 ;
        RECT  0 41.52 0.084 41.544 ;
    END
  END rx_payload[389]
  PIN rx_payload[38]
    DIRECTION INPUT ;
    USE SIGNAL ;
    PORT
      LAYER M4 ;
        RECT  0 7.344 0.084 7.368 ;
    END
  END rx_payload[38]
  PIN rx_payload[390]
    DIRECTION INPUT ;
    USE SIGNAL ;
    PORT
      LAYER M4 ;
        RECT  0 41.664 0.084 41.688 ;
    END
  END rx_payload[390]
  PIN rx_payload[391]
    DIRECTION INPUT ;
    USE SIGNAL ;
    PORT
      LAYER M4 ;
        RECT  0 41.76 0.084 41.784 ;
    END
  END rx_payload[391]
  PIN rx_payload[392]
    DIRECTION INPUT ;
    USE SIGNAL ;
    PORT
      LAYER M4 ;
        RECT  0 41.856 0.084 41.88 ;
    END
  END rx_payload[392]
  PIN rx_payload[393]
    DIRECTION INPUT ;
    USE SIGNAL ;
    PORT
      LAYER M4 ;
        RECT  0 41.952 0.084 41.976 ;
    END
  END rx_payload[393]
  PIN rx_payload[394]
    DIRECTION INPUT ;
    USE SIGNAL ;
    PORT
      LAYER M4 ;
        RECT  0 42.048 0.084 42.072 ;
    END
  END rx_payload[394]
  PIN rx_payload[395]
    DIRECTION INPUT ;
    USE SIGNAL ;
    PORT
      LAYER M4 ;
        RECT  0 42.144 0.084 42.168 ;
    END
  END rx_payload[395]
  PIN rx_payload[396]
    DIRECTION INPUT ;
    USE SIGNAL ;
    PORT
      LAYER M4 ;
        RECT  0 42.24 0.084 42.264 ;
    END
  END rx_payload[396]
  PIN rx_payload[397]
    DIRECTION INPUT ;
    USE SIGNAL ;
    PORT
      LAYER M4 ;
        RECT  0 42.336 0.084 42.36 ;
    END
  END rx_payload[397]
  PIN rx_payload[398]
    DIRECTION INPUT ;
    USE SIGNAL ;
    PORT
      LAYER M4 ;
        RECT  0 42.432 0.084 42.456 ;
    END
  END rx_payload[398]
  PIN rx_payload[399]
    DIRECTION INPUT ;
    USE SIGNAL ;
    PORT
      LAYER M4 ;
        RECT  0 42.528 0.084 42.552 ;
    END
  END rx_payload[399]
  PIN rx_payload[39]
    DIRECTION INPUT ;
    USE SIGNAL ;
    PORT
      LAYER M4 ;
        RECT  0 7.44 0.084 7.464 ;
    END
  END rx_payload[39]
  PIN rx_payload[3]
    DIRECTION INPUT ;
    USE SIGNAL ;
    PORT
      LAYER M4 ;
        RECT  0 3.936 0.084 3.96 ;
    END
  END rx_payload[3]
  PIN rx_payload[400]
    DIRECTION INPUT ;
    USE SIGNAL ;
    PORT
      LAYER M4 ;
        RECT  0 42.624 0.084 42.648 ;
    END
  END rx_payload[400]
  PIN rx_payload[401]
    DIRECTION INPUT ;
    USE SIGNAL ;
    PORT
      LAYER M4 ;
        RECT  0 42.72 0.084 42.744 ;
    END
  END rx_payload[401]
  PIN rx_payload[402]
    DIRECTION INPUT ;
    USE SIGNAL ;
    PORT
      LAYER M4 ;
        RECT  0 42.816 0.084 42.84 ;
    END
  END rx_payload[402]
  PIN rx_payload[403]
    DIRECTION INPUT ;
    USE SIGNAL ;
    PORT
      LAYER M4 ;
        RECT  0 42.912 0.084 42.936 ;
    END
  END rx_payload[403]
  PIN rx_payload[404]
    DIRECTION INPUT ;
    USE SIGNAL ;
    PORT
      LAYER M4 ;
        RECT  0 43.008 0.084 43.032 ;
    END
  END rx_payload[404]
  PIN rx_payload[405]
    DIRECTION INPUT ;
    USE SIGNAL ;
    PORT
      LAYER M4 ;
        RECT  0 43.104 0.084 43.128 ;
    END
  END rx_payload[405]
  PIN rx_payload[406]
    DIRECTION INPUT ;
    USE SIGNAL ;
    PORT
      LAYER M4 ;
        RECT  0 43.2 0.084 43.224 ;
    END
  END rx_payload[406]
  PIN rx_payload[407]
    DIRECTION INPUT ;
    USE SIGNAL ;
    PORT
      LAYER M4 ;
        RECT  0 43.296 0.084 43.32 ;
    END
  END rx_payload[407]
  PIN rx_payload[408]
    DIRECTION INPUT ;
    USE SIGNAL ;
    PORT
      LAYER M4 ;
        RECT  0 43.392 0.084 43.416 ;
    END
  END rx_payload[408]
  PIN rx_payload[409]
    DIRECTION INPUT ;
    USE SIGNAL ;
    PORT
      LAYER M4 ;
        RECT  0 43.488 0.084 43.512 ;
    END
  END rx_payload[409]
  PIN rx_payload[40]
    DIRECTION INPUT ;
    USE SIGNAL ;
    PORT
      LAYER M4 ;
        RECT  0 7.536 0.084 7.56 ;
    END
  END rx_payload[40]
  PIN rx_payload[410]
    DIRECTION INPUT ;
    USE SIGNAL ;
    PORT
      LAYER M4 ;
        RECT  0 43.584 0.084 43.608 ;
    END
  END rx_payload[410]
  PIN rx_payload[411]
    DIRECTION INPUT ;
    USE SIGNAL ;
    PORT
      LAYER M4 ;
        RECT  0 43.68 0.084 43.704 ;
    END
  END rx_payload[411]
  PIN rx_payload[412]
    DIRECTION INPUT ;
    USE SIGNAL ;
    PORT
      LAYER M4 ;
        RECT  0 43.776 0.084 43.8 ;
    END
  END rx_payload[412]
  PIN rx_payload[413]
    DIRECTION INPUT ;
    USE SIGNAL ;
    PORT
      LAYER M4 ;
        RECT  0 43.872 0.084 43.896 ;
    END
  END rx_payload[413]
  PIN rx_payload[414]
    DIRECTION INPUT ;
    USE SIGNAL ;
    PORT
      LAYER M4 ;
        RECT  0 43.968 0.084 43.992 ;
    END
  END rx_payload[414]
  PIN rx_payload[415]
    DIRECTION INPUT ;
    USE SIGNAL ;
    PORT
      LAYER M4 ;
        RECT  0 44.064 0.084 44.088 ;
    END
  END rx_payload[415]
  PIN rx_payload[416]
    DIRECTION INPUT ;
    USE SIGNAL ;
    PORT
      LAYER M4 ;
        RECT  0 44.16 0.084 44.184 ;
    END
  END rx_payload[416]
  PIN rx_payload[417]
    DIRECTION INPUT ;
    USE SIGNAL ;
    PORT
      LAYER M4 ;
        RECT  0 44.256 0.084 44.28 ;
    END
  END rx_payload[417]
  PIN rx_payload[418]
    DIRECTION INPUT ;
    USE SIGNAL ;
    PORT
      LAYER M4 ;
        RECT  0 44.352 0.084 44.376 ;
    END
  END rx_payload[418]
  PIN rx_payload[419]
    DIRECTION INPUT ;
    USE SIGNAL ;
    PORT
      LAYER M4 ;
        RECT  0 44.448 0.084 44.472 ;
    END
  END rx_payload[419]
  PIN rx_payload[41]
    DIRECTION INPUT ;
    USE SIGNAL ;
    PORT
      LAYER M4 ;
        RECT  0 7.632 0.084 7.656 ;
    END
  END rx_payload[41]
  PIN rx_payload[420]
    DIRECTION INPUT ;
    USE SIGNAL ;
    PORT
      LAYER M4 ;
        RECT  0 44.544 0.084 44.568 ;
    END
  END rx_payload[420]
  PIN rx_payload[421]
    DIRECTION INPUT ;
    USE SIGNAL ;
    PORT
      LAYER M4 ;
        RECT  0 44.64 0.084 44.664 ;
    END
  END rx_payload[421]
  PIN rx_payload[422]
    DIRECTION INPUT ;
    USE SIGNAL ;
    PORT
      LAYER M4 ;
        RECT  0 44.736 0.084 44.76 ;
    END
  END rx_payload[422]
  PIN rx_payload[423]
    DIRECTION INPUT ;
    USE SIGNAL ;
    PORT
      LAYER M4 ;
        RECT  0 44.88 0.084 44.904 ;
    END
  END rx_payload[423]
  PIN rx_payload[424]
    DIRECTION INPUT ;
    USE SIGNAL ;
    PORT
      LAYER M4 ;
        RECT  0 44.976 0.084 45 ;
    END
  END rx_payload[424]
  PIN rx_payload[425]
    DIRECTION INPUT ;
    USE SIGNAL ;
    PORT
      LAYER M4 ;
        RECT  0 45.072 0.084 45.096 ;
    END
  END rx_payload[425]
  PIN rx_payload[426]
    DIRECTION INPUT ;
    USE SIGNAL ;
    PORT
      LAYER M4 ;
        RECT  0 45.168 0.084 45.192 ;
    END
  END rx_payload[426]
  PIN rx_payload[427]
    DIRECTION INPUT ;
    USE SIGNAL ;
    PORT
      LAYER M4 ;
        RECT  0 45.264 0.084 45.288 ;
    END
  END rx_payload[427]
  PIN rx_payload[428]
    DIRECTION INPUT ;
    USE SIGNAL ;
    PORT
      LAYER M4 ;
        RECT  0 45.36 0.084 45.384 ;
    END
  END rx_payload[428]
  PIN rx_payload[429]
    DIRECTION INPUT ;
    USE SIGNAL ;
    PORT
      LAYER M4 ;
        RECT  0 45.456 0.084 45.48 ;
    END
  END rx_payload[429]
  PIN rx_payload[42]
    DIRECTION INPUT ;
    USE SIGNAL ;
    PORT
      LAYER M4 ;
        RECT  0 7.728 0.084 7.752 ;
    END
  END rx_payload[42]
  PIN rx_payload[430]
    DIRECTION INPUT ;
    USE SIGNAL ;
    PORT
      LAYER M4 ;
        RECT  0 45.552 0.084 45.576 ;
    END
  END rx_payload[430]
  PIN rx_payload[431]
    DIRECTION INPUT ;
    USE SIGNAL ;
    PORT
      LAYER M4 ;
        RECT  0 45.648 0.084 45.672 ;
    END
  END rx_payload[431]
  PIN rx_payload[432]
    DIRECTION INPUT ;
    USE SIGNAL ;
    PORT
      LAYER M4 ;
        RECT  0 45.744 0.084 45.768 ;
    END
  END rx_payload[432]
  PIN rx_payload[433]
    DIRECTION INPUT ;
    USE SIGNAL ;
    PORT
      LAYER M4 ;
        RECT  0 45.84 0.084 45.864 ;
    END
  END rx_payload[433]
  PIN rx_payload[434]
    DIRECTION INPUT ;
    USE SIGNAL ;
    PORT
      LAYER M4 ;
        RECT  0 45.936 0.084 45.96 ;
    END
  END rx_payload[434]
  PIN rx_payload[435]
    DIRECTION INPUT ;
    USE SIGNAL ;
    PORT
      LAYER M4 ;
        RECT  0 46.032 0.084 46.056 ;
    END
  END rx_payload[435]
  PIN rx_payload[436]
    DIRECTION INPUT ;
    USE SIGNAL ;
    PORT
      LAYER M4 ;
        RECT  0 46.128 0.084 46.152 ;
    END
  END rx_payload[436]
  PIN rx_payload[437]
    DIRECTION INPUT ;
    USE SIGNAL ;
    PORT
      LAYER M4 ;
        RECT  0 46.224 0.084 46.248 ;
    END
  END rx_payload[437]
  PIN rx_payload[438]
    DIRECTION INPUT ;
    USE SIGNAL ;
    PORT
      LAYER M4 ;
        RECT  0 46.32 0.084 46.344 ;
    END
  END rx_payload[438]
  PIN rx_payload[439]
    DIRECTION INPUT ;
    USE SIGNAL ;
    PORT
      LAYER M4 ;
        RECT  0 46.416 0.084 46.44 ;
    END
  END rx_payload[439]
  PIN rx_payload[43]
    DIRECTION INPUT ;
    USE SIGNAL ;
    PORT
      LAYER M4 ;
        RECT  0 7.824 0.084 7.848 ;
    END
  END rx_payload[43]
  PIN rx_payload[440]
    DIRECTION INPUT ;
    USE SIGNAL ;
    PORT
      LAYER M4 ;
        RECT  0 46.512 0.084 46.536 ;
    END
  END rx_payload[440]
  PIN rx_payload[441]
    DIRECTION INPUT ;
    USE SIGNAL ;
    PORT
      LAYER M4 ;
        RECT  0 46.608 0.084 46.632 ;
    END
  END rx_payload[441]
  PIN rx_payload[442]
    DIRECTION INPUT ;
    USE SIGNAL ;
    PORT
      LAYER M4 ;
        RECT  0 46.704 0.084 46.728 ;
    END
  END rx_payload[442]
  PIN rx_payload[443]
    DIRECTION INPUT ;
    USE SIGNAL ;
    PORT
      LAYER M4 ;
        RECT  0 46.8 0.084 46.824 ;
    END
  END rx_payload[443]
  PIN rx_payload[444]
    DIRECTION INPUT ;
    USE SIGNAL ;
    PORT
      LAYER M4 ;
        RECT  0 46.896 0.084 46.92 ;
    END
  END rx_payload[444]
  PIN rx_payload[445]
    DIRECTION INPUT ;
    USE SIGNAL ;
    PORT
      LAYER M4 ;
        RECT  0 46.992 0.084 47.016 ;
    END
  END rx_payload[445]
  PIN rx_payload[446]
    DIRECTION INPUT ;
    USE SIGNAL ;
    PORT
      LAYER M4 ;
        RECT  0 47.088 0.084 47.112 ;
    END
  END rx_payload[446]
  PIN rx_payload[447]
    DIRECTION INPUT ;
    USE SIGNAL ;
    PORT
      LAYER M4 ;
        RECT  0 47.184 0.084 47.208 ;
    END
  END rx_payload[447]
  PIN rx_payload[448]
    DIRECTION INPUT ;
    USE SIGNAL ;
    PORT
      LAYER M4 ;
        RECT  0 47.28 0.084 47.304 ;
    END
  END rx_payload[448]
  PIN rx_payload[449]
    DIRECTION INPUT ;
    USE SIGNAL ;
    PORT
      LAYER M4 ;
        RECT  0 47.376 0.084 47.4 ;
    END
  END rx_payload[449]
  PIN rx_payload[44]
    DIRECTION INPUT ;
    USE SIGNAL ;
    PORT
      LAYER M4 ;
        RECT  0 7.92 0.084 7.944 ;
    END
  END rx_payload[44]
  PIN rx_payload[450]
    DIRECTION INPUT ;
    USE SIGNAL ;
    PORT
      LAYER M4 ;
        RECT  0 47.472 0.084 47.496 ;
    END
  END rx_payload[450]
  PIN rx_payload[451]
    DIRECTION INPUT ;
    USE SIGNAL ;
    PORT
      LAYER M4 ;
        RECT  0 47.568 0.084 47.592 ;
    END
  END rx_payload[451]
  PIN rx_payload[452]
    DIRECTION INPUT ;
    USE SIGNAL ;
    PORT
      LAYER M4 ;
        RECT  0 47.664 0.084 47.688 ;
    END
  END rx_payload[452]
  PIN rx_payload[453]
    DIRECTION INPUT ;
    USE SIGNAL ;
    PORT
      LAYER M4 ;
        RECT  0 47.76 0.084 47.784 ;
    END
  END rx_payload[453]
  PIN rx_payload[454]
    DIRECTION INPUT ;
    USE SIGNAL ;
    PORT
      LAYER M4 ;
        RECT  0 47.856 0.084 47.88 ;
    END
  END rx_payload[454]
  PIN rx_payload[455]
    DIRECTION INPUT ;
    USE SIGNAL ;
    PORT
      LAYER M4 ;
        RECT  0 47.952 0.084 47.976 ;
    END
  END rx_payload[455]
  PIN rx_payload[456]
    DIRECTION INPUT ;
    USE SIGNAL ;
    PORT
      LAYER M4 ;
        RECT  0 48.096 0.084 48.12 ;
    END
  END rx_payload[456]
  PIN rx_payload[457]
    DIRECTION INPUT ;
    USE SIGNAL ;
    PORT
      LAYER M4 ;
        RECT  0 48.192 0.084 48.216 ;
    END
  END rx_payload[457]
  PIN rx_payload[458]
    DIRECTION INPUT ;
    USE SIGNAL ;
    PORT
      LAYER M4 ;
        RECT  0 48.288 0.084 48.312 ;
    END
  END rx_payload[458]
  PIN rx_payload[459]
    DIRECTION INPUT ;
    USE SIGNAL ;
    PORT
      LAYER M4 ;
        RECT  0 48.384 0.084 48.408 ;
    END
  END rx_payload[459]
  PIN rx_payload[45]
    DIRECTION INPUT ;
    USE SIGNAL ;
    PORT
      LAYER M4 ;
        RECT  0 8.016 0.084 8.04 ;
    END
  END rx_payload[45]
  PIN rx_payload[460]
    DIRECTION INPUT ;
    USE SIGNAL ;
    PORT
      LAYER M4 ;
        RECT  0 48.48 0.084 48.504 ;
    END
  END rx_payload[460]
  PIN rx_payload[461]
    DIRECTION INPUT ;
    USE SIGNAL ;
    PORT
      LAYER M4 ;
        RECT  0 48.576 0.084 48.6 ;
    END
  END rx_payload[461]
  PIN rx_payload[462]
    DIRECTION INPUT ;
    USE SIGNAL ;
    PORT
      LAYER M4 ;
        RECT  0 48.672 0.084 48.696 ;
    END
  END rx_payload[462]
  PIN rx_payload[463]
    DIRECTION INPUT ;
    USE SIGNAL ;
    PORT
      LAYER M4 ;
        RECT  0 48.768 0.084 48.792 ;
    END
  END rx_payload[463]
  PIN rx_payload[464]
    DIRECTION INPUT ;
    USE SIGNAL ;
    PORT
      LAYER M4 ;
        RECT  0 48.864 0.084 48.888 ;
    END
  END rx_payload[464]
  PIN rx_payload[465]
    DIRECTION INPUT ;
    USE SIGNAL ;
    PORT
      LAYER M4 ;
        RECT  0 48.96 0.084 48.984 ;
    END
  END rx_payload[465]
  PIN rx_payload[466]
    DIRECTION INPUT ;
    USE SIGNAL ;
    PORT
      LAYER M4 ;
        RECT  0 49.056 0.084 49.08 ;
    END
  END rx_payload[466]
  PIN rx_payload[467]
    DIRECTION INPUT ;
    USE SIGNAL ;
    PORT
      LAYER M4 ;
        RECT  0 49.152 0.084 49.176 ;
    END
  END rx_payload[467]
  PIN rx_payload[468]
    DIRECTION INPUT ;
    USE SIGNAL ;
    PORT
      LAYER M4 ;
        RECT  0 49.248 0.084 49.272 ;
    END
  END rx_payload[468]
  PIN rx_payload[469]
    DIRECTION INPUT ;
    USE SIGNAL ;
    PORT
      LAYER M4 ;
        RECT  0 49.344 0.084 49.368 ;
    END
  END rx_payload[469]
  PIN rx_payload[46]
    DIRECTION INPUT ;
    USE SIGNAL ;
    PORT
      LAYER M4 ;
        RECT  0 8.112 0.084 8.136 ;
    END
  END rx_payload[46]
  PIN rx_payload[470]
    DIRECTION INPUT ;
    USE SIGNAL ;
    PORT
      LAYER M4 ;
        RECT  0 49.44 0.084 49.464 ;
    END
  END rx_payload[470]
  PIN rx_payload[471]
    DIRECTION INPUT ;
    USE SIGNAL ;
    PORT
      LAYER M4 ;
        RECT  0 49.536 0.084 49.56 ;
    END
  END rx_payload[471]
  PIN rx_payload[472]
    DIRECTION INPUT ;
    USE SIGNAL ;
    PORT
      LAYER M4 ;
        RECT  0 49.632 0.084 49.656 ;
    END
  END rx_payload[472]
  PIN rx_payload[473]
    DIRECTION INPUT ;
    USE SIGNAL ;
    PORT
      LAYER M4 ;
        RECT  0 49.728 0.084 49.752 ;
    END
  END rx_payload[473]
  PIN rx_payload[474]
    DIRECTION INPUT ;
    USE SIGNAL ;
    PORT
      LAYER M4 ;
        RECT  0 49.824 0.084 49.848 ;
    END
  END rx_payload[474]
  PIN rx_payload[475]
    DIRECTION INPUT ;
    USE SIGNAL ;
    PORT
      LAYER M4 ;
        RECT  0 49.92 0.084 49.944 ;
    END
  END rx_payload[475]
  PIN rx_payload[476]
    DIRECTION INPUT ;
    USE SIGNAL ;
    PORT
      LAYER M4 ;
        RECT  0 50.016 0.084 50.04 ;
    END
  END rx_payload[476]
  PIN rx_payload[477]
    DIRECTION INPUT ;
    USE SIGNAL ;
    PORT
      LAYER M4 ;
        RECT  0 50.112 0.084 50.136 ;
    END
  END rx_payload[477]
  PIN rx_payload[478]
    DIRECTION INPUT ;
    USE SIGNAL ;
    PORT
      LAYER M4 ;
        RECT  0 50.208 0.084 50.232 ;
    END
  END rx_payload[478]
  PIN rx_payload[479]
    DIRECTION INPUT ;
    USE SIGNAL ;
    PORT
      LAYER M4 ;
        RECT  0 50.304 0.084 50.328 ;
    END
  END rx_payload[479]
  PIN rx_payload[47]
    DIRECTION INPUT ;
    USE SIGNAL ;
    PORT
      LAYER M4 ;
        RECT  0 8.208 0.084 8.232 ;
    END
  END rx_payload[47]
  PIN rx_payload[480]
    DIRECTION INPUT ;
    USE SIGNAL ;
    PORT
      LAYER M4 ;
        RECT  0 50.4 0.084 50.424 ;
    END
  END rx_payload[480]
  PIN rx_payload[481]
    DIRECTION INPUT ;
    USE SIGNAL ;
    PORT
      LAYER M4 ;
        RECT  0 50.496 0.084 50.52 ;
    END
  END rx_payload[481]
  PIN rx_payload[482]
    DIRECTION INPUT ;
    USE SIGNAL ;
    PORT
      LAYER M4 ;
        RECT  0 50.592 0.084 50.616 ;
    END
  END rx_payload[482]
  PIN rx_payload[483]
    DIRECTION INPUT ;
    USE SIGNAL ;
    PORT
      LAYER M4 ;
        RECT  0 50.688 0.084 50.712 ;
    END
  END rx_payload[483]
  PIN rx_payload[484]
    DIRECTION INPUT ;
    USE SIGNAL ;
    PORT
      LAYER M4 ;
        RECT  0 50.784 0.084 50.808 ;
    END
  END rx_payload[484]
  PIN rx_payload[485]
    DIRECTION INPUT ;
    USE SIGNAL ;
    PORT
      LAYER M4 ;
        RECT  0 50.88 0.084 50.904 ;
    END
  END rx_payload[485]
  PIN rx_payload[486]
    DIRECTION INPUT ;
    USE SIGNAL ;
    PORT
      LAYER M4 ;
        RECT  0 50.976 0.084 51 ;
    END
  END rx_payload[486]
  PIN rx_payload[487]
    DIRECTION INPUT ;
    USE SIGNAL ;
    PORT
      LAYER M4 ;
        RECT  0 51.072 0.084 51.096 ;
    END
  END rx_payload[487]
  PIN rx_payload[488]
    DIRECTION INPUT ;
    USE SIGNAL ;
    PORT
      LAYER M4 ;
        RECT  0 51.168 0.084 51.192 ;
    END
  END rx_payload[488]
  PIN rx_payload[489]
    DIRECTION INPUT ;
    USE SIGNAL ;
    PORT
      LAYER M4 ;
        RECT  0 51.264 0.084 51.288 ;
    END
  END rx_payload[489]
  PIN rx_payload[48]
    DIRECTION INPUT ;
    USE SIGNAL ;
    PORT
      LAYER M4 ;
        RECT  0 8.304 0.084 8.328 ;
    END
  END rx_payload[48]
  PIN rx_payload[490]
    DIRECTION INPUT ;
    USE SIGNAL ;
    PORT
      LAYER M4 ;
        RECT  0 51.408 0.084 51.432 ;
    END
  END rx_payload[490]
  PIN rx_payload[491]
    DIRECTION INPUT ;
    USE SIGNAL ;
    PORT
      LAYER M4 ;
        RECT  0 51.504 0.084 51.528 ;
    END
  END rx_payload[491]
  PIN rx_payload[492]
    DIRECTION INPUT ;
    USE SIGNAL ;
    PORT
      LAYER M4 ;
        RECT  0 51.6 0.084 51.624 ;
    END
  END rx_payload[492]
  PIN rx_payload[493]
    DIRECTION INPUT ;
    USE SIGNAL ;
    PORT
      LAYER M4 ;
        RECT  0 51.696 0.084 51.72 ;
    END
  END rx_payload[493]
  PIN rx_payload[494]
    DIRECTION INPUT ;
    USE SIGNAL ;
    PORT
      LAYER M4 ;
        RECT  0 51.792 0.084 51.816 ;
    END
  END rx_payload[494]
  PIN rx_payload[495]
    DIRECTION INPUT ;
    USE SIGNAL ;
    PORT
      LAYER M4 ;
        RECT  0 51.888 0.084 51.912 ;
    END
  END rx_payload[495]
  PIN rx_payload[496]
    DIRECTION INPUT ;
    USE SIGNAL ;
    PORT
      LAYER M4 ;
        RECT  0 51.984 0.084 52.008 ;
    END
  END rx_payload[496]
  PIN rx_payload[497]
    DIRECTION INPUT ;
    USE SIGNAL ;
    PORT
      LAYER M4 ;
        RECT  0 52.08 0.084 52.104 ;
    END
  END rx_payload[497]
  PIN rx_payload[498]
    DIRECTION INPUT ;
    USE SIGNAL ;
    PORT
      LAYER M4 ;
        RECT  0 52.176 0.084 52.2 ;
    END
  END rx_payload[498]
  PIN rx_payload[499]
    DIRECTION INPUT ;
    USE SIGNAL ;
    PORT
      LAYER M4 ;
        RECT  0 52.272 0.084 52.296 ;
    END
  END rx_payload[499]
  PIN rx_payload[49]
    DIRECTION INPUT ;
    USE SIGNAL ;
    PORT
      LAYER M4 ;
        RECT  0 8.4 0.084 8.424 ;
    END
  END rx_payload[49]
  PIN rx_payload[4]
    DIRECTION INPUT ;
    USE SIGNAL ;
    PORT
      LAYER M4 ;
        RECT  0 4.032 0.084 4.056 ;
    END
  END rx_payload[4]
  PIN rx_payload[500]
    DIRECTION INPUT ;
    USE SIGNAL ;
    PORT
      LAYER M4 ;
        RECT  0 52.368 0.084 52.392 ;
    END
  END rx_payload[500]
  PIN rx_payload[501]
    DIRECTION INPUT ;
    USE SIGNAL ;
    PORT
      LAYER M4 ;
        RECT  0 52.464 0.084 52.488 ;
    END
  END rx_payload[501]
  PIN rx_payload[502]
    DIRECTION INPUT ;
    USE SIGNAL ;
    PORT
      LAYER M4 ;
        RECT  0 52.56 0.084 52.584 ;
    END
  END rx_payload[502]
  PIN rx_payload[503]
    DIRECTION INPUT ;
    USE SIGNAL ;
    PORT
      LAYER M4 ;
        RECT  0 52.656 0.084 52.68 ;
    END
  END rx_payload[503]
  PIN rx_payload[504]
    DIRECTION INPUT ;
    USE SIGNAL ;
    PORT
      LAYER M4 ;
        RECT  0 52.752 0.084 52.776 ;
    END
  END rx_payload[504]
  PIN rx_payload[505]
    DIRECTION INPUT ;
    USE SIGNAL ;
    PORT
      LAYER M4 ;
        RECT  0 52.848 0.084 52.872 ;
    END
  END rx_payload[505]
  PIN rx_payload[506]
    DIRECTION INPUT ;
    USE SIGNAL ;
    PORT
      LAYER M4 ;
        RECT  0 52.944 0.084 52.968 ;
    END
  END rx_payload[506]
  PIN rx_payload[507]
    DIRECTION INPUT ;
    USE SIGNAL ;
    PORT
      LAYER M4 ;
        RECT  0 53.04 0.084 53.064 ;
    END
  END rx_payload[507]
  PIN rx_payload[508]
    DIRECTION INPUT ;
    USE SIGNAL ;
    PORT
      LAYER M4 ;
        RECT  0 53.136 0.084 53.16 ;
    END
  END rx_payload[508]
  PIN rx_payload[509]
    DIRECTION INPUT ;
    USE SIGNAL ;
    PORT
      LAYER M4 ;
        RECT  0 53.232 0.084 53.256 ;
    END
  END rx_payload[509]
  PIN rx_payload[50]
    DIRECTION INPUT ;
    USE SIGNAL ;
    PORT
      LAYER M4 ;
        RECT  0 8.496 0.084 8.52 ;
    END
  END rx_payload[50]
  PIN rx_payload[510]
    DIRECTION INPUT ;
    USE SIGNAL ;
    PORT
      LAYER M4 ;
        RECT  0 53.328 0.084 53.352 ;
    END
  END rx_payload[510]
  PIN rx_payload[511]
    DIRECTION INPUT ;
    USE SIGNAL ;
    PORT
      LAYER M4 ;
        RECT  0 53.424 0.084 53.448 ;
    END
  END rx_payload[511]
  PIN rx_payload[512]
    DIRECTION INPUT ;
    USE SIGNAL ;
    PORT
      LAYER M4 ;
        RECT  0 53.52 0.084 53.544 ;
    END
  END rx_payload[512]
  PIN rx_payload[513]
    DIRECTION INPUT ;
    USE SIGNAL ;
    PORT
      LAYER M4 ;
        RECT  0 53.616 0.084 53.64 ;
    END
  END rx_payload[513]
  PIN rx_payload[514]
    DIRECTION INPUT ;
    USE SIGNAL ;
    PORT
      LAYER M4 ;
        RECT  0 53.712 0.084 53.736 ;
    END
  END rx_payload[514]
  PIN rx_payload[515]
    DIRECTION INPUT ;
    USE SIGNAL ;
    PORT
      LAYER M4 ;
        RECT  0 53.808 0.084 53.832 ;
    END
  END rx_payload[515]
  PIN rx_payload[516]
    DIRECTION INPUT ;
    USE SIGNAL ;
    PORT
      LAYER M4 ;
        RECT  0 53.904 0.084 53.928 ;
    END
  END rx_payload[516]
  PIN rx_payload[517]
    DIRECTION INPUT ;
    USE SIGNAL ;
    PORT
      LAYER M4 ;
        RECT  0 54 0.084 54.024 ;
    END
  END rx_payload[517]
  PIN rx_payload[518]
    DIRECTION INPUT ;
    USE SIGNAL ;
    PORT
      LAYER M4 ;
        RECT  0 54.096 0.084 54.12 ;
    END
  END rx_payload[518]
  PIN rx_payload[519]
    DIRECTION INPUT ;
    USE SIGNAL ;
    PORT
      LAYER M4 ;
        RECT  0 54.192 0.084 54.216 ;
    END
  END rx_payload[519]
  PIN rx_payload[51]
    DIRECTION INPUT ;
    USE SIGNAL ;
    PORT
      LAYER M4 ;
        RECT  0 8.592 0.084 8.616 ;
    END
  END rx_payload[51]
  PIN rx_payload[520]
    DIRECTION INPUT ;
    USE SIGNAL ;
    PORT
      LAYER M4 ;
        RECT  0 54.288 0.084 54.312 ;
    END
  END rx_payload[520]
  PIN rx_payload[521]
    DIRECTION INPUT ;
    USE SIGNAL ;
    PORT
      LAYER M4 ;
        RECT  0 54.384 0.084 54.408 ;
    END
  END rx_payload[521]
  PIN rx_payload[522]
    DIRECTION INPUT ;
    USE SIGNAL ;
    PORT
      LAYER M4 ;
        RECT  0 54.48 0.084 54.504 ;
    END
  END rx_payload[522]
  PIN rx_payload[523]
    DIRECTION INPUT ;
    USE SIGNAL ;
    PORT
      LAYER M4 ;
        RECT  0 54.624 0.084 54.648 ;
    END
  END rx_payload[523]
  PIN rx_payload[524]
    DIRECTION INPUT ;
    USE SIGNAL ;
    PORT
      LAYER M4 ;
        RECT  0 54.72 0.084 54.744 ;
    END
  END rx_payload[524]
  PIN rx_payload[525]
    DIRECTION INPUT ;
    USE SIGNAL ;
    PORT
      LAYER M4 ;
        RECT  0 54.816 0.084 54.84 ;
    END
  END rx_payload[525]
  PIN rx_payload[526]
    DIRECTION INPUT ;
    USE SIGNAL ;
    PORT
      LAYER M4 ;
        RECT  0 54.912 0.084 54.936 ;
    END
  END rx_payload[526]
  PIN rx_payload[527]
    DIRECTION INPUT ;
    USE SIGNAL ;
    PORT
      LAYER M4 ;
        RECT  0 55.008 0.084 55.032 ;
    END
  END rx_payload[527]
  PIN rx_payload[528]
    DIRECTION INPUT ;
    USE SIGNAL ;
    PORT
      LAYER M4 ;
        RECT  0 55.104 0.084 55.128 ;
    END
  END rx_payload[528]
  PIN rx_payload[529]
    DIRECTION INPUT ;
    USE SIGNAL ;
    PORT
      LAYER M4 ;
        RECT  0 55.2 0.084 55.224 ;
    END
  END rx_payload[529]
  PIN rx_payload[52]
    DIRECTION INPUT ;
    USE SIGNAL ;
    PORT
      LAYER M4 ;
        RECT  0 8.688 0.084 8.712 ;
    END
  END rx_payload[52]
  PIN rx_payload[530]
    DIRECTION INPUT ;
    USE SIGNAL ;
    PORT
      LAYER M4 ;
        RECT  0 55.296 0.084 55.32 ;
    END
  END rx_payload[530]
  PIN rx_payload[531]
    DIRECTION INPUT ;
    USE SIGNAL ;
    PORT
      LAYER M4 ;
        RECT  0 55.392 0.084 55.416 ;
    END
  END rx_payload[531]
  PIN rx_payload[532]
    DIRECTION INPUT ;
    USE SIGNAL ;
    PORT
      LAYER M4 ;
        RECT  0 55.488 0.084 55.512 ;
    END
  END rx_payload[532]
  PIN rx_payload[533]
    DIRECTION INPUT ;
    USE SIGNAL ;
    PORT
      LAYER M4 ;
        RECT  0 55.584 0.084 55.608 ;
    END
  END rx_payload[533]
  PIN rx_payload[534]
    DIRECTION INPUT ;
    USE SIGNAL ;
    PORT
      LAYER M4 ;
        RECT  0 55.68 0.084 55.704 ;
    END
  END rx_payload[534]
  PIN rx_payload[535]
    DIRECTION INPUT ;
    USE SIGNAL ;
    PORT
      LAYER M4 ;
        RECT  0 55.776 0.084 55.8 ;
    END
  END rx_payload[535]
  PIN rx_payload[536]
    DIRECTION INPUT ;
    USE SIGNAL ;
    PORT
      LAYER M4 ;
        RECT  0 55.872 0.084 55.896 ;
    END
  END rx_payload[536]
  PIN rx_payload[537]
    DIRECTION INPUT ;
    USE SIGNAL ;
    PORT
      LAYER M4 ;
        RECT  0 55.968 0.084 55.992 ;
    END
  END rx_payload[537]
  PIN rx_payload[538]
    DIRECTION INPUT ;
    USE SIGNAL ;
    PORT
      LAYER M4 ;
        RECT  0 56.064 0.084 56.088 ;
    END
  END rx_payload[538]
  PIN rx_payload[539]
    DIRECTION INPUT ;
    USE SIGNAL ;
    PORT
      LAYER M4 ;
        RECT  0 56.16 0.084 56.184 ;
    END
  END rx_payload[539]
  PIN rx_payload[53]
    DIRECTION INPUT ;
    USE SIGNAL ;
    PORT
      LAYER M4 ;
        RECT  0 8.784 0.084 8.808 ;
    END
  END rx_payload[53]
  PIN rx_payload[540]
    DIRECTION INPUT ;
    USE SIGNAL ;
    PORT
      LAYER M4 ;
        RECT  0 56.256 0.084 56.28 ;
    END
  END rx_payload[540]
  PIN rx_payload[541]
    DIRECTION INPUT ;
    USE SIGNAL ;
    PORT
      LAYER M4 ;
        RECT  0 56.352 0.084 56.376 ;
    END
  END rx_payload[541]
  PIN rx_payload[542]
    DIRECTION INPUT ;
    USE SIGNAL ;
    PORT
      LAYER M4 ;
        RECT  0 56.448 0.084 56.472 ;
    END
  END rx_payload[542]
  PIN rx_payload[543]
    DIRECTION INPUT ;
    USE SIGNAL ;
    PORT
      LAYER M4 ;
        RECT  0 56.544 0.084 56.568 ;
    END
  END rx_payload[543]
  PIN rx_payload[544]
    DIRECTION INPUT ;
    USE SIGNAL ;
    PORT
      LAYER M4 ;
        RECT  0 56.64 0.084 56.664 ;
    END
  END rx_payload[544]
  PIN rx_payload[545]
    DIRECTION INPUT ;
    USE SIGNAL ;
    PORT
      LAYER M4 ;
        RECT  0 56.736 0.084 56.76 ;
    END
  END rx_payload[545]
  PIN rx_payload[546]
    DIRECTION INPUT ;
    USE SIGNAL ;
    PORT
      LAYER M4 ;
        RECT  0 56.832 0.084 56.856 ;
    END
  END rx_payload[546]
  PIN rx_payload[547]
    DIRECTION INPUT ;
    USE SIGNAL ;
    PORT
      LAYER M4 ;
        RECT  0 56.928 0.084 56.952 ;
    END
  END rx_payload[547]
  PIN rx_payload[54]
    DIRECTION INPUT ;
    USE SIGNAL ;
    PORT
      LAYER M4 ;
        RECT  0 8.88 0.084 8.904 ;
    END
  END rx_payload[54]
  PIN rx_payload[55]
    DIRECTION INPUT ;
    USE SIGNAL ;
    PORT
      LAYER M4 ;
        RECT  0 8.976 0.084 9 ;
    END
  END rx_payload[55]
  PIN rx_payload[56]
    DIRECTION INPUT ;
    USE SIGNAL ;
    PORT
      LAYER M4 ;
        RECT  0 9.072 0.084 9.096 ;
    END
  END rx_payload[56]
  PIN rx_payload[57]
    DIRECTION INPUT ;
    USE SIGNAL ;
    PORT
      LAYER M4 ;
        RECT  0 9.168 0.084 9.192 ;
    END
  END rx_payload[57]
  PIN rx_payload[58]
    DIRECTION INPUT ;
    USE SIGNAL ;
    PORT
      LAYER M4 ;
        RECT  0 9.312 0.084 9.336 ;
    END
  END rx_payload[58]
  PIN rx_payload[59]
    DIRECTION INPUT ;
    USE SIGNAL ;
    PORT
      LAYER M4 ;
        RECT  0 9.408 0.084 9.432 ;
    END
  END rx_payload[59]
  PIN rx_payload[5]
    DIRECTION INPUT ;
    USE SIGNAL ;
    PORT
      LAYER M4 ;
        RECT  0 4.128 0.084 4.152 ;
    END
  END rx_payload[5]
  PIN rx_payload[60]
    DIRECTION INPUT ;
    USE SIGNAL ;
    PORT
      LAYER M4 ;
        RECT  0 9.504 0.084 9.528 ;
    END
  END rx_payload[60]
  PIN rx_payload[61]
    DIRECTION INPUT ;
    USE SIGNAL ;
    PORT
      LAYER M4 ;
        RECT  0 9.6 0.084 9.624 ;
    END
  END rx_payload[61]
  PIN rx_payload[62]
    DIRECTION INPUT ;
    USE SIGNAL ;
    PORT
      LAYER M4 ;
        RECT  0 9.696 0.084 9.72 ;
    END
  END rx_payload[62]
  PIN rx_payload[63]
    DIRECTION INPUT ;
    USE SIGNAL ;
    PORT
      LAYER M4 ;
        RECT  0 9.792 0.084 9.816 ;
    END
  END rx_payload[63]
  PIN rx_payload[64]
    DIRECTION INPUT ;
    USE SIGNAL ;
    PORT
      LAYER M4 ;
        RECT  0 9.888 0.084 9.912 ;
    END
  END rx_payload[64]
  PIN rx_payload[65]
    DIRECTION INPUT ;
    USE SIGNAL ;
    PORT
      LAYER M4 ;
        RECT  0 9.984 0.084 10.008 ;
    END
  END rx_payload[65]
  PIN rx_payload[66]
    DIRECTION INPUT ;
    USE SIGNAL ;
    PORT
      LAYER M4 ;
        RECT  0 10.08 0.084 10.104 ;
    END
  END rx_payload[66]
  PIN rx_payload[67]
    DIRECTION INPUT ;
    USE SIGNAL ;
    PORT
      LAYER M4 ;
        RECT  0 10.176 0.084 10.2 ;
    END
  END rx_payload[67]
  PIN rx_payload[68]
    DIRECTION INPUT ;
    USE SIGNAL ;
    PORT
      LAYER M4 ;
        RECT  0 10.272 0.084 10.296 ;
    END
  END rx_payload[68]
  PIN rx_payload[69]
    DIRECTION INPUT ;
    USE SIGNAL ;
    PORT
      LAYER M4 ;
        RECT  0 10.368 0.084 10.392 ;
    END
  END rx_payload[69]
  PIN rx_payload[6]
    DIRECTION INPUT ;
    USE SIGNAL ;
    PORT
      LAYER M4 ;
        RECT  0 4.224 0.084 4.248 ;
    END
  END rx_payload[6]
  PIN rx_payload[70]
    DIRECTION INPUT ;
    USE SIGNAL ;
    PORT
      LAYER M4 ;
        RECT  0 10.464 0.084 10.488 ;
    END
  END rx_payload[70]
  PIN rx_payload[71]
    DIRECTION INPUT ;
    USE SIGNAL ;
    PORT
      LAYER M4 ;
        RECT  0 10.56 0.084 10.584 ;
    END
  END rx_payload[71]
  PIN rx_payload[72]
    DIRECTION INPUT ;
    USE SIGNAL ;
    PORT
      LAYER M4 ;
        RECT  0 10.656 0.084 10.68 ;
    END
  END rx_payload[72]
  PIN rx_payload[73]
    DIRECTION INPUT ;
    USE SIGNAL ;
    PORT
      LAYER M4 ;
        RECT  0 10.752 0.084 10.776 ;
    END
  END rx_payload[73]
  PIN rx_payload[74]
    DIRECTION INPUT ;
    USE SIGNAL ;
    PORT
      LAYER M4 ;
        RECT  0 10.848 0.084 10.872 ;
    END
  END rx_payload[74]
  PIN rx_payload[75]
    DIRECTION INPUT ;
    USE SIGNAL ;
    PORT
      LAYER M4 ;
        RECT  0 10.944 0.084 10.968 ;
    END
  END rx_payload[75]
  PIN rx_payload[76]
    DIRECTION INPUT ;
    USE SIGNAL ;
    PORT
      LAYER M4 ;
        RECT  0 11.04 0.084 11.064 ;
    END
  END rx_payload[76]
  PIN rx_payload[77]
    DIRECTION INPUT ;
    USE SIGNAL ;
    PORT
      LAYER M4 ;
        RECT  0 11.136 0.084 11.16 ;
    END
  END rx_payload[77]
  PIN rx_payload[78]
    DIRECTION INPUT ;
    USE SIGNAL ;
    PORT
      LAYER M4 ;
        RECT  0 11.232 0.084 11.256 ;
    END
  END rx_payload[78]
  PIN rx_payload[79]
    DIRECTION INPUT ;
    USE SIGNAL ;
    PORT
      LAYER M4 ;
        RECT  0 11.328 0.084 11.352 ;
    END
  END rx_payload[79]
  PIN rx_payload[7]
    DIRECTION INPUT ;
    USE SIGNAL ;
    PORT
      LAYER M4 ;
        RECT  0 4.32 0.084 4.344 ;
    END
  END rx_payload[7]
  PIN rx_payload[80]
    DIRECTION INPUT ;
    USE SIGNAL ;
    PORT
      LAYER M4 ;
        RECT  0 11.424 0.084 11.448 ;
    END
  END rx_payload[80]
  PIN rx_payload[81]
    DIRECTION INPUT ;
    USE SIGNAL ;
    PORT
      LAYER M4 ;
        RECT  0 11.52 0.084 11.544 ;
    END
  END rx_payload[81]
  PIN rx_payload[82]
    DIRECTION INPUT ;
    USE SIGNAL ;
    PORT
      LAYER M4 ;
        RECT  0 11.616 0.084 11.64 ;
    END
  END rx_payload[82]
  PIN rx_payload[83]
    DIRECTION INPUT ;
    USE SIGNAL ;
    PORT
      LAYER M4 ;
        RECT  0 11.712 0.084 11.736 ;
    END
  END rx_payload[83]
  PIN rx_payload[84]
    DIRECTION INPUT ;
    USE SIGNAL ;
    PORT
      LAYER M4 ;
        RECT  0 11.808 0.084 11.832 ;
    END
  END rx_payload[84]
  PIN rx_payload[85]
    DIRECTION INPUT ;
    USE SIGNAL ;
    PORT
      LAYER M4 ;
        RECT  0 11.904 0.084 11.928 ;
    END
  END rx_payload[85]
  PIN rx_payload[86]
    DIRECTION INPUT ;
    USE SIGNAL ;
    PORT
      LAYER M4 ;
        RECT  0 12 0.084 12.024 ;
    END
  END rx_payload[86]
  PIN rx_payload[87]
    DIRECTION INPUT ;
    USE SIGNAL ;
    PORT
      LAYER M4 ;
        RECT  0 12.096 0.084 12.12 ;
    END
  END rx_payload[87]
  PIN rx_payload[88]
    DIRECTION INPUT ;
    USE SIGNAL ;
    PORT
      LAYER M4 ;
        RECT  0 12.192 0.084 12.216 ;
    END
  END rx_payload[88]
  PIN rx_payload[89]
    DIRECTION INPUT ;
    USE SIGNAL ;
    PORT
      LAYER M4 ;
        RECT  0 12.288 0.084 12.312 ;
    END
  END rx_payload[89]
  PIN rx_payload[8]
    DIRECTION INPUT ;
    USE SIGNAL ;
    PORT
      LAYER M4 ;
        RECT  0 4.416 0.084 4.44 ;
    END
  END rx_payload[8]
  PIN rx_payload[90]
    DIRECTION INPUT ;
    USE SIGNAL ;
    PORT
      LAYER M4 ;
        RECT  0 12.384 0.084 12.408 ;
    END
  END rx_payload[90]
  PIN rx_payload[91]
    DIRECTION INPUT ;
    USE SIGNAL ;
    PORT
      LAYER M4 ;
        RECT  0 12.528 0.084 12.552 ;
    END
  END rx_payload[91]
  PIN rx_payload[92]
    DIRECTION INPUT ;
    USE SIGNAL ;
    PORT
      LAYER M4 ;
        RECT  0 12.624 0.084 12.648 ;
    END
  END rx_payload[92]
  PIN rx_payload[93]
    DIRECTION INPUT ;
    USE SIGNAL ;
    PORT
      LAYER M4 ;
        RECT  0 12.72 0.084 12.744 ;
    END
  END rx_payload[93]
  PIN rx_payload[94]
    DIRECTION INPUT ;
    USE SIGNAL ;
    PORT
      LAYER M4 ;
        RECT  0 12.816 0.084 12.84 ;
    END
  END rx_payload[94]
  PIN rx_payload[95]
    DIRECTION INPUT ;
    USE SIGNAL ;
    PORT
      LAYER M4 ;
        RECT  0 12.912 0.084 12.936 ;
    END
  END rx_payload[95]
  PIN rx_payload[96]
    DIRECTION INPUT ;
    USE SIGNAL ;
    PORT
      LAYER M4 ;
        RECT  0 13.008 0.084 13.032 ;
    END
  END rx_payload[96]
  PIN rx_payload[97]
    DIRECTION INPUT ;
    USE SIGNAL ;
    PORT
      LAYER M4 ;
        RECT  0 13.104 0.084 13.128 ;
    END
  END rx_payload[97]
  PIN rx_payload[98]
    DIRECTION INPUT ;
    USE SIGNAL ;
    PORT
      LAYER M4 ;
        RECT  0 13.2 0.084 13.224 ;
    END
  END rx_payload[98]
  PIN rx_payload[99]
    DIRECTION INPUT ;
    USE SIGNAL ;
    PORT
      LAYER M4 ;
        RECT  0 13.296 0.084 13.32 ;
    END
  END rx_payload[99]
  PIN rx_payload[9]
    DIRECTION INPUT ;
    USE SIGNAL ;
    PORT
      LAYER M4 ;
        RECT  0 4.512 0.084 4.536 ;
    END
  END rx_payload[9]
  PIN VDD
    DIRECTION INOUT ;
    USE POWER ;
    PORT
      LAYER M5 ;
        RECT  40.392 2.151 40.512 95.049 ;
        RECT  34.992 2.151 35.112 95.049 ;
        RECT  29.592 2.151 29.712 95.049 ;
        RECT  24.192 2.151 24.312 95.049 ;
        RECT  18.792 2.151 18.912 95.049 ;
        RECT  13.392 2.151 13.512 95.049 ;
        RECT  7.992 2.151 8.112 95.049 ;
        RECT  2.592 2.151 2.712 95.049 ;
    END
  END VDD
  PIN VSS
    DIRECTION INOUT ;
    USE GROUND ;
    PORT
      LAYER M5 ;
        RECT  40.2 2.137 40.32 95.063 ;
        RECT  34.8 2.137 34.92 95.063 ;
        RECT  29.4 2.137 29.52 95.063 ;
        RECT  24 2.137 24.12 95.063 ;
        RECT  18.6 2.137 18.72 95.063 ;
        RECT  13.2 2.137 13.32 95.063 ;
        RECT  7.8 2.137 7.92 95.063 ;
        RECT  2.4 2.137 2.52 95.063 ;
    END
  END VSS
  OBS
    LAYER RVTN ;
     RECT  2.16 2.16 41.04 2.295 ;
     RECT  2.16 2.565 41.04 2.835 ;
     RECT  2.16 3.105 41.04 3.375 ;
     RECT  2.16 3.645 41.04 3.915 ;
     RECT  2.16 4.185 41.04 4.455 ;
     RECT  2.16 4.725 41.04 4.995 ;
     RECT  2.16 5.265 41.04 5.535 ;
     RECT  2.16 5.805 41.04 6.075 ;
     RECT  2.16 6.345 41.04 6.615 ;
     RECT  2.16 6.885 41.04 7.155 ;
     RECT  2.16 7.425 41.04 7.695 ;
     RECT  2.16 7.965 41.04 8.235 ;
     RECT  2.16 8.505 41.04 8.775 ;
     RECT  2.16 9.045 41.04 9.315 ;
     RECT  2.16 9.585 41.04 9.855 ;
     RECT  2.16 10.125 41.04 10.395 ;
     RECT  2.16 10.665 41.04 10.935 ;
     RECT  2.16 11.205 41.04 11.475 ;
     RECT  2.16 11.745 41.04 12.015 ;
     RECT  2.16 12.285 41.04 12.555 ;
     RECT  2.16 12.825 41.04 13.095 ;
     RECT  2.16 13.365 41.04 13.635 ;
     RECT  2.16 13.905 41.04 14.175 ;
     RECT  2.16 14.445 41.04 14.715 ;
     RECT  2.16 14.985 41.04 15.255 ;
     RECT  2.16 15.525 41.04 15.795 ;
     RECT  2.16 16.065 41.04 16.335 ;
     RECT  2.16 16.605 41.04 16.875 ;
     RECT  2.16 17.145 41.04 17.415 ;
     RECT  2.16 17.685 41.04 17.955 ;
     RECT  2.16 18.225 41.04 18.495 ;
     RECT  2.16 18.765 41.04 19.035 ;
     RECT  2.16 19.305 41.04 19.575 ;
     RECT  2.16 19.845 41.04 20.115 ;
     RECT  2.16 20.385 41.04 20.655 ;
     RECT  2.16 20.925 41.04 21.195 ;
     RECT  2.16 21.465 41.04 21.735 ;
     RECT  2.16 22.005 41.04 22.275 ;
     RECT  2.16 22.545 41.04 22.815 ;
     RECT  2.16 23.085 41.04 23.355 ;
     RECT  2.16 23.625 41.04 23.895 ;
     RECT  2.16 24.165 41.04 24.435 ;
     RECT  2.16 24.705 41.04 24.975 ;
     RECT  2.16 25.245 41.04 25.515 ;
     RECT  2.16 25.785 41.04 26.055 ;
     RECT  2.16 26.325 41.04 26.595 ;
     RECT  2.16 26.865 41.04 27.135 ;
     RECT  2.16 27.405 41.04 27.675 ;
     RECT  2.16 27.945 41.04 28.215 ;
     RECT  2.16 28.485 41.04 28.755 ;
     RECT  2.16 29.025 41.04 29.295 ;
     RECT  2.16 29.565 41.04 29.835 ;
     RECT  2.16 30.105 41.04 30.375 ;
     RECT  2.16 30.645 41.04 30.915 ;
     RECT  2.16 31.185 41.04 31.455 ;
     RECT  2.16 31.725 41.04 31.995 ;
     RECT  2.16 32.265 41.04 32.535 ;
     RECT  2.16 32.805 41.04 33.075 ;
     RECT  2.16 33.345 41.04 33.615 ;
     RECT  2.16 33.885 41.04 34.155 ;
     RECT  2.16 34.425 41.04 34.695 ;
     RECT  2.16 34.965 41.04 35.235 ;
     RECT  2.16 35.505 41.04 35.775 ;
     RECT  2.16 36.045 41.04 36.315 ;
     RECT  2.16 36.585 41.04 36.855 ;
     RECT  2.16 37.125 41.04 37.395 ;
     RECT  2.16 37.665 41.04 37.935 ;
     RECT  2.16 38.205 41.04 38.475 ;
     RECT  2.16 38.745 41.04 39.015 ;
     RECT  2.16 39.285 41.04 39.555 ;
     RECT  2.16 39.825 41.04 40.095 ;
     RECT  2.16 40.365 41.04 40.635 ;
     RECT  2.16 40.905 41.04 41.175 ;
     RECT  2.16 41.445 41.04 41.715 ;
     RECT  2.16 41.985 41.04 42.255 ;
     RECT  2.16 42.525 41.04 42.795 ;
     RECT  2.16 43.065 41.04 43.335 ;
     RECT  2.16 43.605 41.04 43.875 ;
     RECT  2.16 44.145 41.04 44.415 ;
     RECT  2.16 44.685 41.04 44.955 ;
     RECT  2.16 45.225 41.04 45.495 ;
     RECT  2.16 45.765 41.04 46.035 ;
     RECT  2.16 46.305 41.04 46.575 ;
     RECT  2.16 46.845 41.04 47.115 ;
     RECT  2.16 47.385 41.04 47.655 ;
     RECT  2.16 47.925 41.04 48.195 ;
     RECT  2.16 48.465 41.04 48.735 ;
     RECT  2.16 49.005 41.04 49.275 ;
     RECT  2.16 49.545 41.04 49.815 ;
     RECT  2.16 50.085 41.04 50.355 ;
     RECT  2.16 50.625 41.04 50.895 ;
     RECT  2.16 51.165 41.04 51.435 ;
     RECT  2.16 51.705 41.04 51.975 ;
     RECT  2.16 52.245 41.04 52.515 ;
     RECT  2.16 52.785 41.04 53.055 ;
     RECT  2.16 53.325 41.04 53.595 ;
     RECT  2.16 53.865 41.04 54.135 ;
     RECT  2.16 54.405 41.04 54.675 ;
     RECT  2.16 54.945 41.04 55.215 ;
     RECT  2.16 55.485 41.04 55.755 ;
     RECT  2.16 56.025 41.04 56.295 ;
     RECT  2.16 56.565 41.04 56.835 ;
     RECT  2.16 57.105 41.04 57.375 ;
     RECT  2.16 57.645 41.04 57.915 ;
     RECT  2.16 58.185 41.04 58.455 ;
     RECT  2.16 58.725 41.04 58.995 ;
     RECT  2.16 59.265 41.04 59.535 ;
     RECT  2.16 59.805 41.04 60.075 ;
     RECT  2.16 60.345 41.04 60.615 ;
     RECT  2.16 60.885 41.04 61.155 ;
     RECT  2.16 61.425 41.04 61.695 ;
     RECT  2.16 61.965 41.04 62.235 ;
     RECT  2.16 62.505 41.04 62.775 ;
     RECT  2.16 63.045 41.04 63.315 ;
     RECT  2.16 63.585 41.04 63.855 ;
     RECT  2.16 64.125 41.04 64.395 ;
     RECT  2.16 64.665 41.04 64.935 ;
     RECT  2.16 65.205 41.04 65.475 ;
     RECT  2.16 65.745 41.04 66.015 ;
     RECT  2.16 66.285 41.04 66.555 ;
     RECT  2.16 66.825 41.04 67.095 ;
     RECT  2.16 67.365 41.04 67.635 ;
     RECT  2.16 67.905 41.04 68.175 ;
     RECT  2.16 68.445 41.04 68.715 ;
     RECT  2.16 68.985 41.04 69.255 ;
     RECT  2.16 69.525 41.04 69.795 ;
     RECT  2.16 70.065 41.04 70.335 ;
     RECT  2.16 70.605 41.04 70.875 ;
     RECT  2.16 71.145 41.04 71.415 ;
     RECT  2.16 71.685 41.04 71.955 ;
     RECT  2.16 72.225 41.04 72.495 ;
     RECT  2.16 72.765 41.04 73.035 ;
     RECT  2.16 73.305 41.04 73.575 ;
     RECT  2.16 73.845 41.04 74.115 ;
     RECT  2.16 74.385 41.04 74.655 ;
     RECT  2.16 74.925 41.04 75.195 ;
     RECT  2.16 75.465 41.04 75.735 ;
     RECT  2.16 76.005 41.04 76.275 ;
     RECT  2.16 76.545 41.04 76.815 ;
     RECT  2.16 77.085 41.04 77.355 ;
     RECT  2.16 77.625 41.04 77.895 ;
     RECT  2.16 78.165 41.04 78.435 ;
     RECT  2.16 78.705 41.04 78.975 ;
     RECT  2.16 79.245 41.04 79.515 ;
     RECT  2.16 79.785 41.04 80.055 ;
     RECT  2.16 80.325 41.04 80.595 ;
     RECT  2.16 80.865 41.04 81.135 ;
     RECT  2.16 81.405 41.04 81.675 ;
     RECT  2.16 81.945 41.04 82.215 ;
     RECT  2.16 82.485 41.04 82.755 ;
     RECT  2.16 83.025 41.04 83.295 ;
     RECT  2.16 83.565 41.04 83.835 ;
     RECT  2.16 84.105 41.04 84.375 ;
     RECT  2.16 84.645 41.04 84.915 ;
     RECT  2.16 85.185 41.04 85.455 ;
     RECT  2.16 85.725 41.04 85.995 ;
     RECT  2.16 86.265 41.04 86.535 ;
     RECT  2.16 86.805 41.04 87.075 ;
     RECT  2.16 87.345 41.04 87.615 ;
     RECT  2.16 87.885 41.04 88.155 ;
     RECT  2.16 88.425 41.04 88.695 ;
     RECT  2.16 88.965 41.04 89.235 ;
     RECT  2.16 89.505 41.04 89.775 ;
     RECT  2.16 90.045 41.04 90.315 ;
     RECT  2.16 90.585 41.04 90.855 ;
     RECT  2.16 91.125 41.04 91.395 ;
     RECT  2.16 91.665 41.04 91.935 ;
     RECT  2.16 92.205 41.04 92.475 ;
     RECT  2.16 92.745 41.04 93.015 ;
     RECT  2.16 93.285 41.04 93.555 ;
     RECT  2.16 93.825 41.04 94.095 ;
     RECT  2.16 94.365 41.04 94.635 ;
     RECT  2.16 94.905 41.04 95.04 ;
    LAYER RVTP ;
     RECT  2.16 2.295 41.04 2.565 ;
     RECT  2.16 2.835 41.04 3.105 ;
     RECT  2.16 3.375 41.04 3.645 ;
     RECT  2.16 3.915 41.04 4.185 ;
     RECT  2.16 4.455 41.04 4.725 ;
     RECT  2.16 4.995 41.04 5.265 ;
     RECT  2.16 5.535 41.04 5.805 ;
     RECT  2.16 6.075 41.04 6.345 ;
     RECT  2.16 6.615 41.04 6.885 ;
     RECT  2.16 7.155 41.04 7.425 ;
     RECT  2.16 7.695 41.04 7.965 ;
     RECT  2.16 8.235 41.04 8.505 ;
     RECT  2.16 8.775 41.04 9.045 ;
     RECT  2.16 9.315 41.04 9.585 ;
     RECT  2.16 9.855 41.04 10.125 ;
     RECT  2.16 10.395 41.04 10.665 ;
     RECT  2.16 10.935 41.04 11.205 ;
     RECT  2.16 11.475 41.04 11.745 ;
     RECT  2.16 12.015 41.04 12.285 ;
     RECT  2.16 12.555 41.04 12.825 ;
     RECT  2.16 13.095 41.04 13.365 ;
     RECT  2.16 13.635 41.04 13.905 ;
     RECT  2.16 14.175 41.04 14.445 ;
     RECT  2.16 14.715 41.04 14.985 ;
     RECT  2.16 15.255 41.04 15.525 ;
     RECT  2.16 15.795 41.04 16.065 ;
     RECT  2.16 16.335 41.04 16.605 ;
     RECT  2.16 16.875 41.04 17.145 ;
     RECT  2.16 17.415 41.04 17.685 ;
     RECT  2.16 17.955 41.04 18.225 ;
     RECT  2.16 18.495 41.04 18.765 ;
     RECT  2.16 19.035 41.04 19.305 ;
     RECT  2.16 19.575 41.04 19.845 ;
     RECT  2.16 20.115 41.04 20.385 ;
     RECT  2.16 20.655 41.04 20.925 ;
     RECT  2.16 21.195 41.04 21.465 ;
     RECT  2.16 21.735 41.04 22.005 ;
     RECT  2.16 22.275 41.04 22.545 ;
     RECT  2.16 22.815 41.04 23.085 ;
     RECT  2.16 23.355 41.04 23.625 ;
     RECT  2.16 23.895 41.04 24.165 ;
     RECT  2.16 24.435 41.04 24.705 ;
     RECT  2.16 24.975 41.04 25.245 ;
     RECT  2.16 25.515 41.04 25.785 ;
     RECT  2.16 26.055 41.04 26.325 ;
     RECT  2.16 26.595 41.04 26.865 ;
     RECT  2.16 27.135 41.04 27.405 ;
     RECT  2.16 27.675 41.04 27.945 ;
     RECT  2.16 28.215 41.04 28.485 ;
     RECT  2.16 28.755 41.04 29.025 ;
     RECT  2.16 29.295 41.04 29.565 ;
     RECT  2.16 29.835 41.04 30.105 ;
     RECT  2.16 30.375 41.04 30.645 ;
     RECT  2.16 30.915 41.04 31.185 ;
     RECT  2.16 31.455 41.04 31.725 ;
     RECT  2.16 31.995 41.04 32.265 ;
     RECT  2.16 32.535 41.04 32.805 ;
     RECT  2.16 33.075 41.04 33.345 ;
     RECT  2.16 33.615 41.04 33.885 ;
     RECT  2.16 34.155 41.04 34.425 ;
     RECT  2.16 34.695 41.04 34.965 ;
     RECT  2.16 35.235 41.04 35.505 ;
     RECT  2.16 35.775 41.04 36.045 ;
     RECT  2.16 36.315 41.04 36.585 ;
     RECT  2.16 36.855 41.04 37.125 ;
     RECT  2.16 37.395 41.04 37.665 ;
     RECT  2.16 37.935 41.04 38.205 ;
     RECT  2.16 38.475 41.04 38.745 ;
     RECT  2.16 39.015 41.04 39.285 ;
     RECT  2.16 39.555 41.04 39.825 ;
     RECT  2.16 40.095 41.04 40.365 ;
     RECT  2.16 40.635 41.04 40.905 ;
     RECT  2.16 41.175 41.04 41.445 ;
     RECT  2.16 41.715 41.04 41.985 ;
     RECT  2.16 42.255 41.04 42.525 ;
     RECT  2.16 42.795 41.04 43.065 ;
     RECT  2.16 43.335 41.04 43.605 ;
     RECT  2.16 43.875 41.04 44.145 ;
     RECT  2.16 44.415 41.04 44.685 ;
     RECT  2.16 44.955 41.04 45.225 ;
     RECT  2.16 45.495 41.04 45.765 ;
     RECT  2.16 46.035 41.04 46.305 ;
     RECT  2.16 46.575 41.04 46.845 ;
     RECT  2.16 47.115 41.04 47.385 ;
     RECT  2.16 47.655 41.04 47.925 ;
     RECT  2.16 48.195 41.04 48.465 ;
     RECT  2.16 48.735 41.04 49.005 ;
     RECT  2.16 49.275 41.04 49.545 ;
     RECT  2.16 49.815 41.04 50.085 ;
     RECT  2.16 50.355 41.04 50.625 ;
     RECT  2.16 50.895 41.04 51.165 ;
     RECT  2.16 51.435 41.04 51.705 ;
     RECT  2.16 51.975 41.04 52.245 ;
     RECT  2.16 52.515 41.04 52.785 ;
     RECT  2.16 53.055 41.04 53.325 ;
     RECT  2.16 53.595 41.04 53.865 ;
     RECT  2.16 54.135 41.04 54.405 ;
     RECT  2.16 54.675 41.04 54.945 ;
     RECT  2.16 55.215 41.04 55.485 ;
     RECT  2.16 55.755 41.04 56.025 ;
     RECT  2.16 56.295 41.04 56.565 ;
     RECT  2.16 56.835 41.04 57.105 ;
     RECT  2.16 57.375 41.04 57.645 ;
     RECT  2.16 57.915 41.04 58.185 ;
     RECT  2.16 58.455 41.04 58.725 ;
     RECT  2.16 58.995 41.04 59.265 ;
     RECT  2.16 59.535 41.04 59.805 ;
     RECT  2.16 60.075 41.04 60.345 ;
     RECT  2.16 60.615 41.04 60.885 ;
     RECT  2.16 61.155 41.04 61.425 ;
     RECT  2.16 61.695 41.04 61.965 ;
     RECT  2.16 62.235 41.04 62.505 ;
     RECT  2.16 62.775 41.04 63.045 ;
     RECT  2.16 63.315 41.04 63.585 ;
     RECT  2.16 63.855 41.04 64.125 ;
     RECT  2.16 64.395 41.04 64.665 ;
     RECT  2.16 64.935 41.04 65.205 ;
     RECT  2.16 65.475 41.04 65.745 ;
     RECT  2.16 66.015 41.04 66.285 ;
     RECT  2.16 66.555 41.04 66.825 ;
     RECT  2.16 67.095 41.04 67.365 ;
     RECT  2.16 67.635 41.04 67.905 ;
     RECT  2.16 68.175 41.04 68.445 ;
     RECT  2.16 68.715 41.04 68.985 ;
     RECT  2.16 69.255 41.04 69.525 ;
     RECT  2.16 69.795 41.04 70.065 ;
     RECT  2.16 70.335 41.04 70.605 ;
     RECT  2.16 70.875 41.04 71.145 ;
     RECT  2.16 71.415 41.04 71.685 ;
     RECT  2.16 71.955 41.04 72.225 ;
     RECT  2.16 72.495 41.04 72.765 ;
     RECT  2.16 73.035 41.04 73.305 ;
     RECT  2.16 73.575 41.04 73.845 ;
     RECT  2.16 74.115 41.04 74.385 ;
     RECT  2.16 74.655 41.04 74.925 ;
     RECT  2.16 75.195 41.04 75.465 ;
     RECT  2.16 75.735 41.04 76.005 ;
     RECT  2.16 76.275 41.04 76.545 ;
     RECT  2.16 76.815 41.04 77.085 ;
     RECT  2.16 77.355 41.04 77.625 ;
     RECT  2.16 77.895 41.04 78.165 ;
     RECT  2.16 78.435 41.04 78.705 ;
     RECT  2.16 78.975 41.04 79.245 ;
     RECT  2.16 79.515 41.04 79.785 ;
     RECT  2.16 80.055 41.04 80.325 ;
     RECT  2.16 80.595 41.04 80.865 ;
     RECT  2.16 81.135 41.04 81.405 ;
     RECT  2.16 81.675 41.04 81.945 ;
     RECT  2.16 82.215 41.04 82.485 ;
     RECT  2.16 82.755 41.04 83.025 ;
     RECT  2.16 83.295 41.04 83.565 ;
     RECT  2.16 83.835 41.04 84.105 ;
     RECT  2.16 84.375 41.04 84.645 ;
     RECT  2.16 84.915 41.04 85.185 ;
     RECT  2.16 85.455 41.04 85.725 ;
     RECT  2.16 85.995 41.04 86.265 ;
     RECT  2.16 86.535 41.04 86.805 ;
     RECT  2.16 87.075 41.04 87.345 ;
     RECT  2.16 87.615 41.04 87.885 ;
     RECT  2.16 88.155 41.04 88.425 ;
     RECT  2.16 88.695 41.04 88.965 ;
     RECT  2.16 89.235 41.04 89.505 ;
     RECT  2.16 89.775 41.04 90.045 ;
     RECT  2.16 90.315 41.04 90.585 ;
     RECT  2.16 90.855 41.04 91.125 ;
     RECT  2.16 91.395 41.04 91.665 ;
     RECT  2.16 91.935 41.04 92.205 ;
     RECT  2.16 92.475 41.04 92.745 ;
     RECT  2.16 93.015 41.04 93.285 ;
     RECT  2.16 93.555 41.04 93.825 ;
     RECT  2.16 94.095 41.04 94.365 ;
     RECT  2.16 94.635 41.04 94.905 ;
    LAYER M1 ;
     RECT  2.16 2.151 41.04 95.049 ;
    LAYER M2 ;
     RECT  0.067 55.071 0.103 55.089 ;
     RECT  0.103 3.69 0.139 3.708 ;
     RECT  0.103 5.202 0.139 5.22 ;
     RECT  0.103 52.83 0.139 52.848 ;
     RECT  0.031 14.796 0.167 14.814 ;
     RECT  0.067 37.062 0.175 37.08 ;
     RECT  0.139 52.56 0.175 52.848 ;
     RECT  0.103 53.946 0.175 56.358 ;
     RECT  0.067 9.324 0.239 9.342 ;
     RECT  0.283 7.362 0.319 7.38 ;
     RECT  0.139 3.042 0.535 5.22 ;
     RECT  0.319 7.362 0.823 7.416 ;
     RECT  0.031 40.842 0.931 40.86 ;
     RECT  1.039 45.81 1.111 45.828 ;
     RECT  1.003 46.62 1.111 46.638 ;
     RECT  0.787 47.7 1.435 47.718 ;
     RECT  0.859 48.672 1.435 48.69 ;
     RECT  0.895 50.022 1.435 50.04 ;
     RECT  0.067 39.636 1.471 39.654 ;
     RECT  0.931 40.536 1.471 40.86 ;
     RECT  0.931 42.732 1.471 42.75 ;
     RECT  0.175 37.062 1.507 37.62 ;
     RECT  0.823 7.056 1.723 7.416 ;
     RECT  1.435 47.7 2.011 50.04 ;
     RECT  1.399 51.102 2.011 51.12 ;
     RECT  0.967 33.282 2.047 33.3 ;
     RECT  1.471 42.57 2.047 42.75 ;
     RECT  2.011 47.7 2.083 51.12 ;
     RECT  0.535 3.042 2.16 5.562 ;
     RECT  1.723 6.552 2.16 7.416 ;
     RECT  2.047 32.742 2.16 33.3 ;
     RECT  1.579 34.362 2.16 34.38 ;
     RECT  1.507 36.522 2.16 37.62 ;
     RECT  0.103 38.376 2.16 38.394 ;
     RECT  1.471 39.636 2.16 40.86 ;
     RECT  2.083 41.652 2.16 41.67 ;
     RECT  2.047 42.57 2.16 43.29 ;
     RECT  0.967 44.19 2.16 44.208 ;
     RECT  1.111 45.81 2.16 46.638 ;
     RECT  2.083 47.628 2.16 51.12 ;
     RECT  0.175 52.56 2.16 56.358 ;
     RECT  2.16 2.151 5.575 95.049 ;
     RECT  5.575 2.106 6.115 95.049 ;
     RECT  6.115 1.998 10.787 95.049 ;
     RECT  10.787 2.07 13.379 95.049 ;
     RECT  13.379 2.151 41.04 95.049 ;
    LAYER M3 ;
     RECT  10.98 0.091 13.158 0.139 ;
     RECT  7.344 0.091 7.722 0.523 ;
     RECT  9.396 0.091 9.414 0.523 ;
     RECT  10.98 0.139 13.626 0.523 ;
     RECT  14.976 0.091 16.326 0.523 ;
     RECT  4.86 0.091 6.57 0.571 ;
     RECT  7.344 0.523 8.19 0.571 ;
     RECT  10.98 0.523 16.326 0.571 ;
     RECT  7.344 0.571 8.478 1.099 ;
     RECT  9.396 0.523 9.594 1.099 ;
     RECT  10.908 0.571 16.326 1.099 ;
     RECT  3.96 0.091 3.978 1.723 ;
     RECT  4.824 0.571 6.57 1.723 ;
     RECT  7.344 1.099 16.326 1.723 ;
     RECT  30.24 1.675 30.258 1.723 ;
     RECT  7.344 1.723 16.614 1.771 ;
     RECT  3.744 1.723 6.57 2.101 ;
     RECT  7.344 1.771 17.01 2.101 ;
     RECT  2.415 2.143 2.505 2.413 ;
     RECT  18.615 2.143 18.705 2.413 ;
     RECT  24.015 2.143 24.105 2.413 ;
     RECT  29.415 2.143 29.505 2.413 ;
     RECT  30.24 1.723 30.726 2.413 ;
     RECT  34.815 2.143 34.905 2.413 ;
     RECT  40.215 2.143 40.305 2.413 ;
     RECT  3.744 2.101 17.01 2.525 ;
     RECT  2.415 2.413 2.697 2.641 ;
     RECT  3.744 2.525 15.426 2.641 ;
     RECT  2.415 2.641 15.426 2.759 ;
     RECT  16.92 2.525 17.01 2.759 ;
     RECT  33.3 1.099 33.318 3.029 ;
     RECT  2.415 2.759 15.39 3.181 ;
     RECT  31.5 3.181 31.518 3.299 ;
     RECT  0.144 3.037 0.162 3.307 ;
     RECT  2.34 3.181 15.39 3.379 ;
     RECT  29.415 2.413 30.726 3.415 ;
     RECT  16.92 2.759 16.938 3.547 ;
     RECT  18.615 2.413 18.897 3.547 ;
     RECT  16.668 3.547 16.938 3.569 ;
     RECT  33.048 3.181 33.21 3.577 ;
     RECT  32.04 3.451 32.058 3.605 ;
     RECT  0.144 3.307 0.198 3.613 ;
     RECT  33.012 3.577 33.21 3.613 ;
     RECT  2.304 3.379 15.39 3.643 ;
     RECT  1.728 3.643 15.39 3.649 ;
     RECT  18.615 3.547 18.99 3.677 ;
     RECT  0.144 3.613 0.558 3.685 ;
     RECT  18.615 3.677 18.897 3.721 ;
     RECT  17.928 3.721 18.897 3.839 ;
     RECT  32.616 3.613 33.21 3.839 ;
     RECT  16.668 3.569 16.686 3.983 ;
     RECT  17.496 3.955 17.514 4.109 ;
     RECT  29.415 3.415 30.87 4.145 ;
     RECT  31.176 4.261 31.194 4.379 ;
     RECT  29.415 4.145 30.294 4.451 ;
     RECT  1.728 3.649 15.786 4.649 ;
     RECT  33.048 3.839 33.066 4.721 ;
     RECT  1.728 4.649 12.078 4.919 ;
     RECT  9.972 4.919 12.078 4.991 ;
     RECT  9.972 4.991 11.97 5.189 ;
     RECT  10.8 5.189 11.682 5.297 ;
     RECT  1.728 4.919 9.234 5.459 ;
     RECT  13.215 4.649 15.39 5.459 ;
     RECT  1.728 5.459 9.126 5.567 ;
     RECT  29.415 4.451 30.222 5.567 ;
     RECT  3.6 5.567 9.126 5.603 ;
     RECT  9.972 5.189 10.026 5.603 ;
     RECT  4.104 5.603 9.126 5.639 ;
     RECT  4.5 5.639 9.126 5.729 ;
     RECT  0.108 3.685 0.558 5.789 ;
     RECT  13.215 5.459 15.21 5.809 ;
     RECT  4.5 5.729 8.838 5.873 ;
     RECT  11.232 5.297 11.682 5.873 ;
     RECT  0.144 5.789 0.558 5.885 ;
     RECT  29.415 5.567 29.934 6.071 ;
     RECT  0.144 5.885 0.486 6.125 ;
     RECT  12.816 5.809 15.21 6.269 ;
     RECT  12.816 6.269 14.886 6.341 ;
     RECT  4.5 5.873 8.586 6.376 ;
     RECT  3.996 6.376 8.586 6.413 ;
     RECT  4.536 6.413 8.586 6.449 ;
     RECT  1.728 5.567 2.826 6.575 ;
     RECT  4.536 6.449 8.262 6.605 ;
     RECT  5.148 6.605 8.262 6.653 ;
     RECT  5.652 6.653 8.262 6.701 ;
     RECT  5.688 6.701 8.262 6.809 ;
     RECT  12.816 6.341 14.85 6.809 ;
     RECT  1.98 6.575 2.826 6.817 ;
     RECT  7.344 6.809 8.262 6.845 ;
     RECT  5.688 6.809 6.246 6.953 ;
     RECT  7.38 6.845 8.262 6.953 ;
     RECT  5.688 6.953 6.21 6.989 ;
     RECT  0.144 6.125 0.162 7.051 ;
     RECT  6.192 6.989 6.21 7.085 ;
     RECT  0.144 7.051 0.846 7.181 ;
     RECT  7.632 6.953 8.097 7.181 ;
     RECT  12.816 6.809 14.49 7.223 ;
     RECT  0.288 7.181 0.846 7.339 ;
     RECT  1.98 6.817 3.366 7.339 ;
     RECT  0.288 7.339 3.366 7.469 ;
     RECT  0.324 7.469 3.366 7.565 ;
     RECT  0.828 7.565 3.366 8.041 ;
     RECT  12.816 7.223 14.418 8.843 ;
     RECT  0.828 8.041 3.51 8.875 ;
     RECT  0.108 8.875 3.51 9.319 ;
     RECT  0.072 9.319 3.51 14.791 ;
     RECT  17.1 22.699 17.118 22.739 ;
     RECT  15.984 22.741 16.002 22.781 ;
     RECT  12.816 8.843 13.497 23.179 ;
     RECT  11.664 5.873 11.682 23.317 ;
     RECT  12.708 23.179 13.497 23.317 ;
     RECT  11.664 23.317 13.497 23.357 ;
     RECT  16.344 23.161 16.362 23.357 ;
     RECT  11.664 23.357 11.682 24.235 ;
     RECT  11.34 24.235 11.682 24.379 ;
     RECT  11.016 24.379 11.682 24.619 ;
     RECT  10.836 24.619 11.682 24.809 ;
     RECT  11.016 24.809 11.682 24.935 ;
     RECT  11.34 24.935 11.682 25.169 ;
     RECT  0.036 14.791 3.51 38.399 ;
     RECT  0.036 38.399 0.054 39.631 ;
     RECT  0.036 39.631 0.09 40.865 ;
     RECT  12.816 23.357 13.497 44.069 ;
     RECT  4.392 8.815 4.41 45.149 ;
     RECT  0.828 38.399 3.51 45.157 ;
     RECT  14.4 8.843 14.418 45.419 ;
     RECT  0.828 45.157 3.978 47.039 ;
     RECT  0.072 40.865 0.09 47.695 ;
     RECT  0.828 47.039 3.834 47.695 ;
     RECT  0.072 47.695 3.834 48.119 ;
     RECT  17.712 47.995 17.73 48.119 ;
     RECT  17.64 48.127 17.658 48.173 ;
     RECT  11.664 25.169 11.682 48.299 ;
     RECT  26.964 3.919 26.982 48.433 ;
     RECT  25.956 48.937 25.974 48.989 ;
     RECT  26.964 48.433 27.018 49.081 ;
     RECT  25.992 49.081 26.118 49.199 ;
     RECT  26.856 49.081 27.018 49.199 ;
     RECT  26.856 49.199 26.874 49.235 ;
     RECT  0.072 48.119 3.51 53.131 ;
     RECT  9.936 5.773 9.954 53.159 ;
     RECT  0.072 53.131 3.546 53.249 ;
     RECT  0.072 53.249 3.51 53.285 ;
     RECT  0.072 53.285 3.474 54.869 ;
     RECT  0.072 54.869 3.366 55.094 ;
     RECT  0.108 55.094 3.366 55.421 ;
     RECT  2.196 55.421 3.366 55.901 ;
     RECT  0.108 55.421 1.458 56.477 ;
     RECT  2.268 55.901 3.366 56.635 ;
     RECT  2.232 56.635 3.366 56.731 ;
     RECT  2.196 56.731 3.366 57.029 ;
     RECT  2.196 57.029 3.078 57.137 ;
     RECT  2.415 57.137 3.078 57.443 ;
     RECT  0.828 56.477 1.458 80.573 ;
     RECT  1.44 80.573 1.458 81.773 ;
     RECT  24.015 2.413 24.297 93.451 ;
     RECT  25.992 49.199 26.01 93.479 ;
     RECT  23.904 93.451 24.297 93.488 ;
     RECT  25.2 93.451 25.218 94.289 ;
     RECT  2.415 57.443 2.697 94.787 ;
     RECT  7.815 7.181 8.097 94.787 ;
     RECT  13.215 44.069 13.497 94.787 ;
     RECT  18.615 3.839 18.897 94.787 ;
     RECT  24.015 93.488 24.297 94.787 ;
     RECT  29.415 6.071 29.697 94.787 ;
     RECT  34.815 2.413 35.097 94.787 ;
     RECT  40.215 2.413 40.497 94.787 ;
     RECT  2.415 94.787 2.505 95.057 ;
     RECT  7.815 94.787 7.905 95.057 ;
     RECT  13.215 94.787 13.305 95.057 ;
     RECT  18.615 94.787 18.705 95.057 ;
     RECT  24.015 94.787 24.105 95.057 ;
     RECT  29.415 94.787 29.505 95.057 ;
     RECT  34.815 94.787 34.905 95.057 ;
     RECT  40.215 94.787 40.305 95.057 ;
     RECT  25.02 94.405 25.038 95.165 ;
    LAYER M4 ;
     RECT  0.06 53.52 0.137 56.952 ;
     RECT  0.06 3.648 0.245 9.336 ;
     RECT  0.137 53.616 0.569 56.952 ;
     RECT  0.06 80.544 0.857 80.568 ;
     RECT  0.245 3.648 0.929 9.192 ;
     RECT  0.929 3.648 2.408 8.808 ;
     RECT  2.293 42.192 2.408 42.216 ;
     RECT  0.569 53.904 2.408 56.952 ;
     RECT  0.06 81.744 2.408 81.768 ;
     RECT  2.408 2.148 2.512 95.052 ;
     RECT  2.512 2.418 2.704 94.782 ;
     RECT  2.704 42.192 2.729 42.216 ;
     RECT  2.704 3.024 2.801 7.944 ;
     RECT  2.704 56.784 2.801 56.808 ;
     RECT  2.704 48.144 2.819 48.168 ;
     RECT  2.704 54.672 2.837 54.696 ;
     RECT  2.801 6.384 2.981 7.944 ;
     RECT  2.704 44.16 3.161 44.184 ;
     RECT  2.801 3.024 3.485 4.632 ;
     RECT  3.733 1.728 3.788 1.752 ;
     RECT  3.485 3.024 3.788 4.344 ;
     RECT  2.981 6.384 4.025 7.176 ;
     RECT  3.788 1.728 4.105 4.344 ;
     RECT  4.105 1.728 4.499 2.28 ;
     RECT  3.949 0.096 4.549 0.12 ;
     RECT  4.499 1.728 5.005 1.848 ;
     RECT  4.105 3.408 5.137 4.344 ;
     RECT  5.137 3.408 5.557 4.536 ;
     RECT  5.557 3.408 5.641 5.16 ;
     RECT  5.641 3.408 5.713 5.256 ;
     RECT  4.025 6.528 5.717 7.176 ;
     RECT  4.549 0.096 5.933 0.6 ;
     RECT  5.713 2.832 6.133 5.256 ;
     RECT  5.005 1.728 6.217 1.8 ;
     RECT  6.133 2.832 6.217 5.736 ;
     RECT  5.717 6.864 6.257 7.176 ;
     RECT  6.217 1.728 6.365 5.736 ;
     RECT  6.365 1.728 7.405 5.208 ;
     RECT  5.933 0.096 7.436 0.12 ;
     RECT  7.405 1.104 7.436 5.208 ;
     RECT  7.436 0.096 7.733 5.208 ;
     RECT  7.733 0.144 7.808 5.208 ;
     RECT  6.257 7.152 7.808 7.176 ;
     RECT  7.669 23.088 7.808 23.112 ;
     RECT  6.901 24.624 7.808 24.648 ;
     RECT  7.808 0.144 7.912 95.052 ;
     RECT  7.912 0.144 8.104 94.782 ;
     RECT  8.104 0.144 8.243 4.488 ;
     RECT  8.243 0.528 8.291 4.488 ;
     RECT  8.291 0.576 8.381 4.488 ;
     RECT  8.381 0.576 8.489 3.432 ;
     RECT  8.381 4.416 8.993 4.488 ;
     RECT  8.489 1.104 9.203 3.432 ;
     RECT  9.341 0.096 9.425 0.12 ;
     RECT  9.203 1.104 9.565 2.616 ;
     RECT  9.565 0.528 9.731 2.616 ;
     RECT  9.731 1.104 10.397 2.616 ;
     RECT  8.993 4.416 10.597 4.44 ;
     RECT  10.397 1.104 10.685 1.8 ;
     RECT  10.597 3.984 10.865 4.44 ;
     RECT  10.853 0.576 10.937 0.6 ;
     RECT  8.104 24.24 11.027 24.648 ;
     RECT  8.104 23.184 11.029 23.208 ;
     RECT  11.027 24.24 11.029 24.408 ;
     RECT  11.029 23.184 11.075 24.408 ;
     RECT  10.865 4.416 11.269 4.44 ;
     RECT  11.075 23.184 11.369 24.264 ;
     RECT  11.269 4.416 11.441 4.584 ;
     RECT  10.685 1.728 11.509 1.8 ;
     RECT  11.509 1.728 11.593 2.328 ;
     RECT  11.593 1.728 11.653 2.28 ;
     RECT  11.653 1.68 11.939 2.28 ;
     RECT  10.969 0.096 11.941 0.168 ;
     RECT  11.939 1.68 12.661 2.04 ;
     RECT  11.941 0.096 13.093 0.552 ;
     RECT  12.661 1.584 13.093 2.04 ;
     RECT  13.093 0.096 13.208 2.04 ;
     RECT  11.441 4.416 13.208 4.44 ;
     RECT  11.369 23.184 13.208 23.352 ;
     RECT  10.981 93.312 13.208 93.336 ;
     RECT  13.208 0.096 13.312 95.052 ;
     RECT  13.312 0.096 13.331 94.782 ;
     RECT  13.331 2.256 13.504 94.782 ;
     RECT  13.331 0.096 13.571 1.176 ;
     RECT  13.571 0.144 13.681 1.176 ;
     RECT  13.504 2.256 14.051 2.328 ;
     RECT  14.051 2.256 14.243 2.28 ;
     RECT  13.681 0.528 14.579 1.176 ;
     RECT  14.579 1.104 14.597 1.176 ;
     RECT  13.504 3.552 14.753 4.44 ;
     RECT  14.597 1.104 14.797 1.8 ;
     RECT  14.797 1.104 15.251 1.752 ;
     RECT  13.504 23.328 15.932 23.352 ;
     RECT  15.932 22.752 16.019 23.352 ;
     RECT  14.821 0.096 16.381 0.12 ;
     RECT  15.251 1.728 16.624 1.752 ;
     RECT  16.624 1.728 16.625 1.8 ;
     RECT  14.753 3.552 16.657 3.576 ;
     RECT  16.657 3.552 16.697 3.672 ;
     RECT  16.625 1.776 17.021 1.8 ;
     RECT  16.019 23.328 17.077 23.352 ;
     RECT  17.077 22.704 17.164 23.352 ;
     RECT  16.213 48 17.317 48.024 ;
     RECT  17.164 23.328 17.363 23.352 ;
     RECT  16.697 3.648 18.608 3.672 ;
     RECT  17.317 48 18.608 48.984 ;
     RECT  13.504 93.456 18.608 93.48 ;
     RECT  18.608 2.148 18.712 95.052 ;
     RECT  18.712 2.418 18.904 94.782 ;
     RECT  18.904 3.552 19.001 3.672 ;
     RECT  18.904 48.144 21.539 48.984 ;
     RECT  19.001 3.552 24.008 3.576 ;
     RECT  21.539 48.96 24.008 48.984 ;
     RECT  18.904 93.456 24.008 93.48 ;
     RECT  24.008 2.148 24.112 95.052 ;
     RECT  24.112 2.418 24.304 95.052 ;
     RECT  24.965 95.136 25.049 95.16 ;
     RECT  24.304 48.96 25.985 48.984 ;
     RECT  24.304 3.552 29.408 3.576 ;
     RECT  29.408 2.148 29.512 95.052 ;
     RECT  29.512 2.148 29.704 94.782 ;
     RECT  30.188 1.68 30.275 1.704 ;
     RECT  30.668 1.728 30.755 1.752 ;
     RECT  29.704 3.456 32.069 3.48 ;
     RECT  33.26 1.104 33.347 1.128 ;
     RECT  34.808 2.148 34.912 95.052 ;
     RECT  34.912 2.418 35.104 94.782 ;
     RECT  40.208 2.148 40.312 95.052 ;
     RECT  40.312 2.418 40.504 94.782 ;
    LAYER M5 ;
     RECT  33.312 0.016 33.336 1.139 ;
     RECT  30.24 0.016 30.744 1.715 ;
     RECT  3.744 0.016 16.68 1.763 ;
     RECT  30.72 1.715 30.744 1.763 ;
     RECT  3.84 1.763 14.76 1.811 ;
     RECT  16.656 1.763 16.68 1.811 ;
     RECT  3.84 1.811 11.928 1.859 ;
     RECT  2.4 2.137 2.52 2.151 ;
     RECT  18.6 2.137 18.72 2.151 ;
     RECT  24 2.137 24.12 2.151 ;
     RECT  34.8 2.137 34.92 2.151 ;
     RECT  40.2 2.137 40.32 2.151 ;
     RECT  3.84 1.859 4.488 2.291 ;
     RECT  5.568 1.859 11.928 2.291 ;
     RECT  13.2 1.811 14.232 2.291 ;
     RECT  5.568 2.291 11.544 2.339 ;
     RECT  13.2 2.291 14.04 2.339 ;
     RECT  5.568 2.339 9.528 2.387 ;
     RECT  3.84 2.291 4.056 2.963 ;
     RECT  2.4 2.151 2.712 3.013 ;
     RECT  3.84 2.963 3.96 3.013 ;
     RECT  5.568 2.387 9.192 3.443 ;
     RECT  2.4 3.013 3.96 3.539 ;
     RECT  13.2 2.339 13.512 3.733 ;
     RECT  10.608 2.339 11.304 4.019 ;
     RECT  13.2 3.733 13.704 4.451 ;
     RECT  11.28 4.019 11.304 4.595 ;
     RECT  2.4 3.539 3.432 4.643 ;
     RECT  5.568 3.443 8.232 5.171 ;
     RECT  5.664 5.171 8.232 5.219 ;
     RECT  6.144 5.219 8.232 5.747 ;
     RECT  2.4 4.643 2.712 6.805 ;
     RECT  2.4 6.805 2.808 7.765 ;
     RECT  15.984 22.741 16.008 23.317 ;
     RECT  17.088 3.637 17.112 23.317 ;
     RECT  15.984 23.317 17.352 23.363 ;
     RECT  6.912 5.747 8.232 24.275 ;
     RECT  11.04 23.317 11.064 24.419 ;
     RECT  6.912 24.275 8.112 24.659 ;
     RECT  2.304 7.765 2.808 42.227 ;
     RECT  16.224 23.363 16.248 48.035 ;
     RECT  2.4 42.227 2.808 48.179 ;
     RECT  17.328 23.363 17.352 48.995 ;
     RECT  10.992 24.613 11.016 93.347 ;
     RECT  2.4 48.179 2.712 95.049 ;
     RECT  7.8 24.659 8.112 95.049 ;
     RECT  13.2 4.451 13.512 95.049 ;
     RECT  18.6 2.151 18.912 95.049 ;
     RECT  29.4 2.137 29.712 95.049 ;
     RECT  34.8 2.151 35.112 95.049 ;
     RECT  40.2 2.151 40.512 95.049 ;
     RECT  2.4 95.049 2.52 95.063 ;
     RECT  7.8 95.049 7.92 95.063 ;
     RECT  13.2 95.049 13.32 95.063 ;
     RECT  18.6 95.049 18.72 95.063 ;
     RECT  24 2.151 24.312 95.063 ;
     RECT  29.4 95.049 29.52 95.063 ;
     RECT  34.8 95.049 34.92 95.063 ;
     RECT  40.2 95.049 40.32 95.063 ;
     RECT  21.504 48.133 21.528 97.168 ;
     RECT  25.008 95.125 25.032 97.168 ;
  END
END qfd_mu_ctx_rx_die
END LIBRARY
